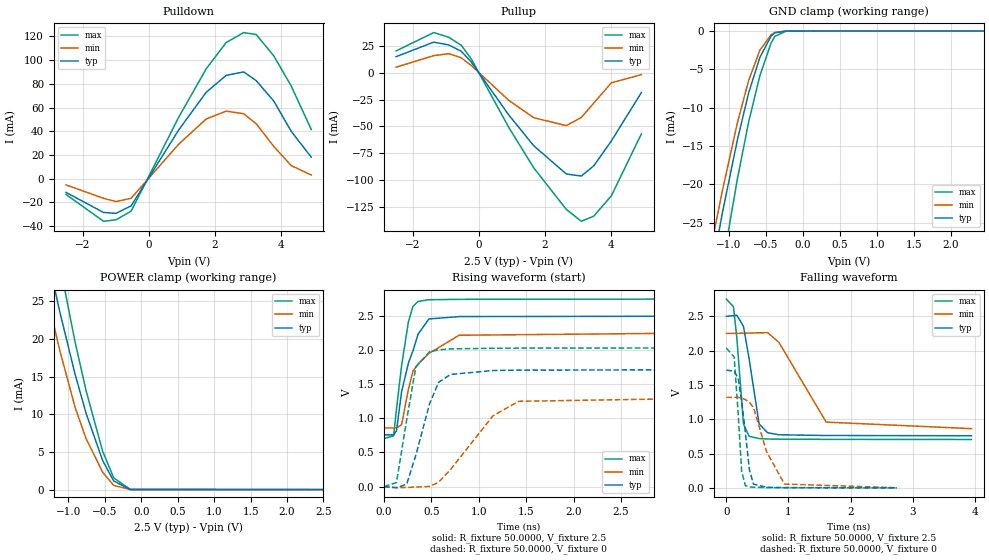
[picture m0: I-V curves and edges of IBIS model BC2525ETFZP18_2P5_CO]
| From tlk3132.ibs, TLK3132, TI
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[Model]   BC2525ETFZP18_2P5_CO
Model_type   I/O
Polarity   Non-Inverting
Enable   Active-Low
Vinl =  0.7V
Vinh =  1.7V
Cref =  15.0000pF
Rref =  100.0000M
Vref =  0V
Vmeas =  1.25
C_comp   2.309127p   2.203225p   2.349335p
[Model Spec]
Vinl   0.7V   0.7V   0.7V
Vinh   1.7V   1.7V   1.7V
[Temperature Range]   25   105   0
[Voltage Range]   2.5   2.25   2.75
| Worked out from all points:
|   slope of the pulldown table from 0 to 0.375 V, typ, clamps not added: 21.4 ohm
|   slope of the pullup table from 0 to 0.375 V, typ, clamps not added: 22.5 ohm
|   GND clamp passes 1 mA (typ) near -0.45 V on its own axis
|   POWER clamp passes 1 mA (typ) near -0.36 V on its own axis
|   rising waveform, R_fixture 50.0000, V_fixture 2.5: 20-80 % time 181ps typ, 269ps min, 118ps max; typ from 0.759 V to 2.5 V
|   rising waveform, R_fixture 50.0000, V_fixture 0: 20-80 % time 203ps typ, 452ps min, 132ps max; typ from 0 V to 1.72 V
|   falling waveform, R_fixture 50.0000, V_fixture 2.5: 20-80 % time 170ps typ, 464ps min, 103ps max; typ from 2.5 V to 0.759 V
|   falling waveform, R_fixture 50.0000, V_fixture 0: 20-80 % time 129ps typ, 290ps min, 78.3ps max; typ from 1.72 V to 0.001 V
[POWER_clamp]
|   voltage   I(typ)   I(min)   I(max)
-2.5V     103mA      79.59mA    127.2mA
-1.414V   37.89mA    31.01mA    46.59mA
-1.389V   36.5mA     29.9mA     44.97mA
-1.263V   30.03mA    24.43mA    37.51mA
-1.136V   24.34mA    19.18mA    30.79mA
-1.111V   23.3mA     18.19mA    29.51mA
-909.1mV  15.33mA    10.94mA    19.61mA
-757.6mV  10.13mA    6.766mA    13.14mA
-530.3mV  3.861mA    2.319mA    5.098mA
-378.8mV  1.145mA    563.9uA    1.555mA
-151.5mV  13.13uA    4.646uA    27.22uA
2.5V      48.25nA    100nA      297nA
[Pulldown]
|   voltage   I(typ)   I(min)   I(max)
-2.5V     -11.51mA   -5.201mA   -13.26mA
-1.364V   -28.43mA   -16.49mA   -35.86mA
-984.8mV  -29.1mA    -19.21mA   -34.52mA
-530.3mV  -22.86mA   -16.47mA   -27.32mA
909.1mV   41.11mA    29.14mA    51.82mA
1.742V    72.89mA    50.39mA    92.67mA
2.348V    87.23mA    57.05mA    114.9mA
2.879V    90.11mA    54.86mA    123.3mA
3.258V    82.75mA    46.36mA    121.6mA
3.788V    65.57mA    27.35mA    103.7mA
4.318V    40.02mA    11.1mA     78.22mA
4.924V    18.22mA    3.195mA    41.6mA
[Pullup]
|   voltage   I(typ)   I(min)   I(max)
-2.5V     15.14mA    5.324mA    20.54mA
-1.364V   28.73mA    16.09mA    37.65mA
-909.1mV  26.11mA    17.93mA    33.27mA
-530.3mV  20.16mA    14.07mA    25.77mA
-227.3mV  10.18mA    6.927mA    13.07mA
909.1mV   -39.37mA   -25.74mA   -51mA
1.667V    -68.19mA   -41.92mA   -88.83mA
2.652V    -94.51mA   -49.32mA   -127.6mA
3.106V    -96.42mA   -41.67mA   -138.7mA
3.485V    -86.79mA   -28.14mA   -133.8mA
4.015V    -63.64mA   -9.302mA   -114.9mA
4.924V    -18.43mA   -1.644mA   -57.08mA
[GND_clamp]
|   voltage   I(typ)   I(min)   I(max)
-2.5V     -116.2mA   -90.94mA   -142.3mA
-1.338V   -38.29mA   -32.95mA   -46.66mA
-1.237V   -32.01mA   -28mA      -39.68mA
-1.136V   -26.24mA   -23.14mA   -33.46mA
-1.086V   -23.65mA   -20.78mA   -30.54mA
-883.8mV  -14.17mA   -11.94mA   -19.27mA
-732.3mV  -8.082mA   -6.459mA   -11.87mA
-580.8mV  -3.458mA   -2.524mA   -5.849mA
-429.3mV  -675uA     -501.2uA   -1.581mA
-378.8mV  -238.8uA   -197.2uA   -699.9uA
-227.3mV  -10.88uA   -11uA      -30.03uA
2.449V    3.342nA    24.03uA    91.08nA
[Ramp]
| variable   typ   min   max
dV/dt_f   1.057917/0.169422n   0.8442267/0.4696358n   1.236219/0.1031428n
dV/dt_r   1.045516/0.2054243n  0.8092633/0.4608445n   1.23592/0.1329528n
R_load = 50
[Rising Waveform]
R_fixture = 50.0000
V_fixture = 2.5
V_fixture_min = 2.25
V_fixture_max = 2.75
|   time   V(typ)   V(min)   V(max)
0s        759.1mV    860.8mV    704.6mV
102ps     757.4mV    860.8mV    745.6mV
132ps     816.5mV    860.7mV    1.134V
186ps     1.39V      906.8mV    1.773V
258ps     1.813V     1.43V      2.418V
306ps     1.991V     1.693V     2.644V
360ps     2.236V     1.799V     2.716V
474ps     2.459V     1.953V     2.741V
792ps     2.494V     2.22V      2.747V
2.97ns    2.499V     2.248V     2.75V
[Rising Waveform]
R_fixture = 50.0000
V_fixture = 0
V_fixture_min = 0
V_fixture_max = 0
|   time   V(typ)   V(min)   V(max)
0s        45.2uV     17.27uV    78.37uV
132ps     -18.97mV   -13.15mV   58.56mV
240ps     35.35mV    -13.65mV   982.2mV
336ps     457.7mV    -6.885mV   1.753V
480ps     1.21V      1.607mV    1.977V
576ps     1.53V      61.71mV    2.006V
702ps     1.645V     250.3mV    2.02V
1.152ns   1.703V     1.041V     2.029V
1.422ns   1.708V     1.251V     2.031V
4.404ns   1.716V     1.317V     2.035V
[Falling Waveform]
R_fixture = 50.0000
V_fixture = 2.5
V_fixture_min = 2.25
V_fixture_max = 2.75
|   time   V(typ)   V(min)   V(max)
0s        2.5V       2.25V      2.75V
114ps     2.509V     2.251V     2.641V
168ps     2.516V     2.252V     2.198V
276ps     2.353V     2.253V     933.6mV
366ps     1.887V     2.255V     752.6mV
528ps     930.2mV    2.26V      718mV
666ps     802.9mV    2.261V     712.3mV
846ps     773.6mV    2.121V     710mV
1.608ns   763mV      958mV      707mV
3.948ns   759.3mV    863.1mV    704.8mV
[Falling Waveform]
R_fixture = 50.0000
V_fixture = 0
V_fixture_min = 0
V_fixture_max = 0
|   time   V(typ)   V(min)   V(max)
0s        1.716V     1.319V     2.036V
126ps     1.698V     1.319V     1.908V
192ps     1.595V     1.317V     1.067V
246ps     1.263V     1.308V     245.1mV
306ps     810.5mV    1.286V     33.03mV
372ps     261mV      1.246V     14.26mV
438ps     54.65mV    1.17V      9.532mV
648ps     8.61mV     528.1mV    3.99mV
936ps     4.158mV    55.55mV    2.047mV
2.748ns   1.02mV     2.275mV    289.4uV
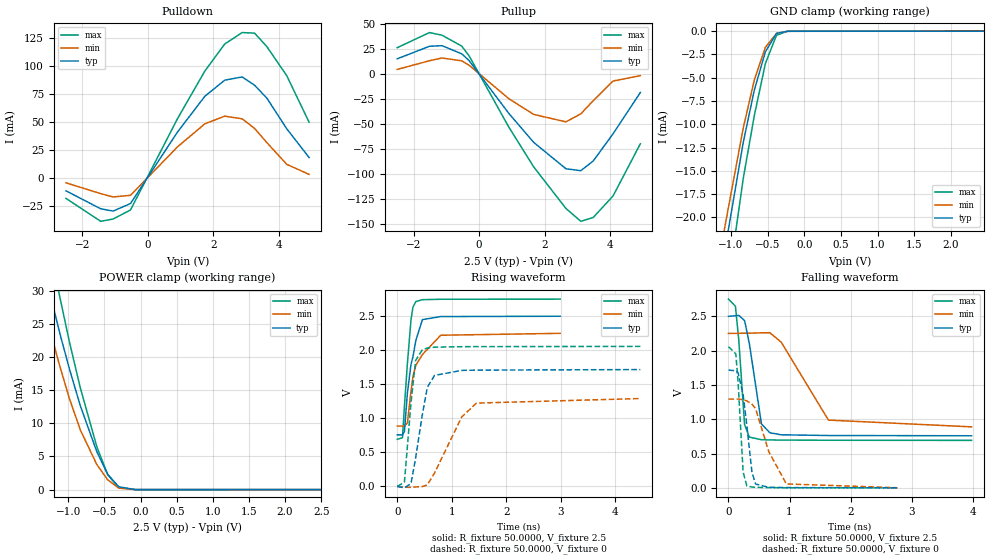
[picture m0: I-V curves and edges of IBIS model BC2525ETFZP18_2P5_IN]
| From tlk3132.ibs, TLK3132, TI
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|   Model Cell BC2525ETFZP18_2P5_IN
|BC2525ETFZP18_2P5
[Model]   BC2525ETFZP18_2P5_IN
Model_type   I/O
Polarity   Non-Inverting
Enable   Active-Low
Vinl =  0.7V
Vinh =  1.7V
Cref =  15.0000pF
Rref =  100.0000M
Vref =  0V
Vmeas =  1.25
C_comp   2.309127p   2.211398p   2.342242p
[Model Spec]
Vinl   0.7V   0.7V   0.7V
Vinh   1.7V   1.7V   1.7V
[Temperature Range]   25   125   -40
[Voltage Range]   2.5   2.25   2.75
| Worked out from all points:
|   slope of the pulldown table from 0 to 0.375 V, typ, clamps not added: 21.4 ohm
|   slope of the pullup table from 0 to 0.375 V, typ, clamps not added: 22.5 ohm
|   GND clamp passes 1 mA (typ) near -0.45 V on its own axis
|   POWER clamp passes 1 mA (typ) near -0.36 V on its own axis
|   rising waveform, R_fixture 50.0000, V_fixture 2.5: 20-80 % time 181ps typ, 272ps min, 113ps max; typ from 0.759 V to 2.5 V
|   rising waveform, R_fixture 50.0000, V_fixture 0: 20-80 % time 204ps typ, 470ps min, 121ps max; typ from 0 V to 1.72 V
|   falling waveform, R_fixture 50.0000, V_fixture 2.5: 20-80 % time 170ps typ, 476ps min, 94.6ps max; typ from 2.5 V to 0.759 V
|   falling waveform, R_fixture 50.0000, V_fixture 0: 20-80 % time 130ps typ, 293ps min, 75.4ps max; typ from 1.72 V to 0.001 V
[POWER_clamp]
|   voltage   I(typ)   I(min)   I(max)
-2.5V     103mA      77mA       124.9mA
-1.389V   36.5mA     29.6mA     43.7mA
-1.364V   35.11mA    28.54mA    42.24mA
-1.237V   28.84mA    23.35mA    35.37mA
-1.111V   23.3mA     18.37mA    28.7mA
-984.8mV  18.21mA    13.73mA    22.28mA
-833.3mV  12.63mA    8.988mA    15.33mA
-606.1mV  5.731mA    3.798mA    6.501mA
-454.5mV  2.303mA    1.469mA    2.233mA
-303mV    430uA      224.9uA    328.4uA
-75.76mV  1.022uA    1.09uA     373.5nA
2.5V      48.25nA    187.9nA    78.52nA
[Pulldown]
|   voltage   I(typ)   I(min)   I(max)
-2.5V     -11.51mA   -4.358mA   -18.24mA
-1.439V   -27.53mA   -14.02mA   -38.69mA
-1.061V   -29.57mA   -16.96mA   -36.64mA
-530.3mV  -22.86mA   -15.51mA   -28.6mA
909.1mV   41.11mA    27.83mA    53.08mA
1.742V    72.89mA    48.31mA    95.41mA
2.348V    87.24mA    55.12mA    119.5mA
2.879V    90.11mA    52.76mA    129.7mA
3.258V    82.75mA    44.23mA    129.2mA
3.636V    71.14mA    31.46mA    117.1mA
4.242V    43.83mA    12.12mA    91.2mA
4.924V    18.23mA    3.165mA    49.73mA
[Pullup]
|   voltage   I(typ)   I(min)   I(max)
-2.5V     15.14mA    4.581mA    26.25mA
-1.515V   27.67mA    13.2mA     41.32mA
-1.136V   28.26mA    15.97mA    38.74mA
-530.3mV  20.16mA    13.13mA    27.83mA
-303mV    13.29mA    8.656mA    17.98mA
909.1mV   -39.37mA   -24.63mA   -53.05mA
1.667V    -68.19mA   -40.33mA   -92.6mA
2.652V    -94.51mA   -47.7mA    -134.1mA
3.106V    -96.42mA   -39.75mA   -146.9mA
3.485V    -86.79mA   -26.62mA   -143.1mA
4.091V    -59.62mA   -7.005mA   -121.6mA
4.924V    -18.43mA   -1.635mA   -69.59mA
[GND_clamp]
|   voltage   I(typ)   I(min)   I(max)
-2.5V     -116.2mA   -88.1mA    -139.9mA
-1.338V   -38.29mA   -32.77mA   -45.08mA
-1.288V   -35.07mA   -30.39mA   -41.92mA
-1.237V   -32.01mA   -28.03mA   -38.88mA
-1.136V   -26.24mA   -23.37mA   -32.85mA
-1.086V   -23.65mA   -21.1mA    -29.88mA
-833.3mV  -11.97mA   -10.43mA   -15.85mA
-681.8mV  -6.338mA   -5.243mA   -9.07mA
-530.3mV  -2.211mA   -1.734mA   -3.467mA
-378.8mV  -238.8uA   -245.9uA   -430.9uA
-227.3mV  -10.88uA   -15.38uA   -15.83uA
2.449V    3.343nA    36.11uA    41.83nA
[Ramp]
| variable   typ   min   max
dV/dt_f   1.057951/0.1693632n  0.8284071/0.4810959n   1.244731/95.26762p
dV/dt_r   1.045398/0.2060787n  0.7933716/0.4786505n   1.248755/0.1217709n
R_load = 50
[Rising Waveform]
R_fixture = 50.0000
V_fixture = 2.5
V_fixture_min = 2.25
V_fixture_max = 2.75
|   time   V(typ)   V(min)   V(max)
0s        759mV      886.7mV    692.1mV
96ps      757.5mV    886.6mV    715.9mV
132ps     805.4mV    886.6mV    1.179V
186ps     1.369V     930.7mV    1.798V
252ps     1.791V     1.394V     2.444V
288ps     1.902V     1.613V     2.631V
342ps     2.147V     1.782V     2.715V
462ps     2.449V     1.937V     2.742V
798ps     2.494V     2.22V      2.748V
2.988ns   2.499V     2.248V     2.75V
[Rising Waveform]
R_fixture = 50.0000
V_fixture = 0
V_fixture_min = 0
V_fixture_max = 0
|   time   V(typ)   V(min)   V(max)
0s        45.2uV     18.9uV     81.41uV
132ps     -20.04mV   -10.69mV   64.09mV
252ps     42.94mV    -13.13mV   1.223V
336ps     410.8mV    -7.215mV   1.848V
462ps     1.064V     -735.1uV   2.008V
552ps     1.455V     23.24mV    2.032V
684ps     1.63V      198.4mV    2.045V
1.182ns   1.704V     1.019V     2.052V
1.452ns   1.708V     1.224V     2.053V
4.458ns   1.716V     1.291V     2.056V
[Falling Waveform]
R_fixture = 50.0000
V_fixture = 2.5
V_fixture_min = 2.25
V_fixture_max = 2.75
|   time   V(typ)   V(min)   V(max)
0s        2.5V       2.25V      2.75V
114ps     2.508V     2.251V     2.646V
168ps     2.514V     2.252V     2.161V
264ps     2.438V     2.253V     921.4mV
342ps     2.103V     2.254V     739.4mV
540ps     932.5mV    2.259V     701.9mV
678ps     803.1mV    2.261V     698.3mV
864ps     773.3mV    2.123V     696.5mV
1.638ns   762.9mV    987.6mV    693.8mV
3.984ns   759.2mV    889mV      692.1mV
[Falling Waveform]
R_fixture = 50.0000
V_fixture = 0
V_fixture_min = 0
V_fixture_max = 0
|   time   V(typ)   V(min)   V(max)
0s        1.716V     1.293V     2.057V
120ps     1.706V     1.293V     1.952V
156ps     1.68V      1.294V     1.562V
240ps     1.359V     1.285V     230.6mV
300ps     916.3mV    1.267V     29.64mV
384ps     231.4mV    1.22V      12.15mV
444ps     55.77mV    1.155V     8.632mV
660ps     8.457mV    529.2mV    3.499mV
948ps     4.117mV    57.37mV    1.807mV
2.766ns   1.011mV    2.28mV     225.2uV
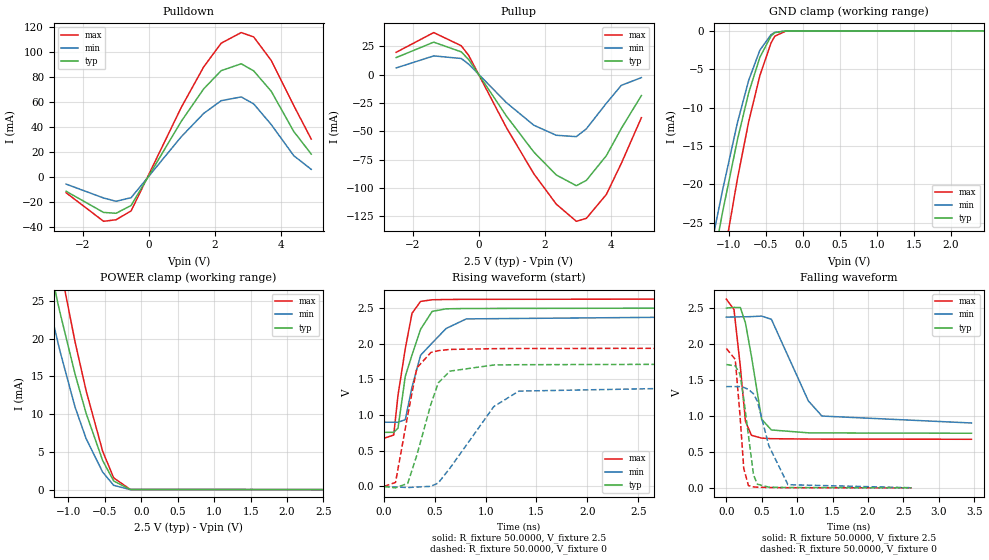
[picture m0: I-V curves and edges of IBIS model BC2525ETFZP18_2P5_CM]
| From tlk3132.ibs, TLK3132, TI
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|   Model Cell BC2525ETFZP18_2P5_CM
|BC2525ETFZP18_2P5
[Model]   BC2525ETFZP18_2P5_CM
Model_type   I/O
Polarity   Non-Inverting
Enable   Active-Low
Vinl =  0.7V
Vinh =  1.7V
Cref =  15.0000pF
Rref =  100.0000M
Vref =  0V
Vmeas =  1.25
C_comp   2.309127p   2.20323p   2.349335p
[Model Spec]
Vinl   0.7V   0.7V   0.7V
Vinh   1.7V   1.7V   1.7V
[Temperature Range]   25   105   0
[Voltage Range]   2.5   2.375   2.625
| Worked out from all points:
|   slope of the pulldown table from 0 to 0.375 V, typ, clamps not added: 21.4 ohm
|   slope of the pullup table from 0 to 0.375 V, typ, clamps not added: 22.5 ohm
|   GND clamp passes 1 mA (typ) near -0.45 V on its own axis
|   POWER clamp passes 1 mA (typ) near -0.36 V on its own axis
|   rising waveform, R_fixture 50.0000, V_fixture 2.5: 20-80 % time 182ps typ, 266ps min, 123ps max; typ from 0.759 V to 2.5 V
|   rising waveform, R_fixture 50.0000, V_fixture 0: 20-80 % time 205ps typ, 422ps min, 138ps max; typ from 0 V to 1.72 V
|   falling waveform, R_fixture 50.0000, V_fixture 2.5: 20-80 % time 168ps typ, 374ps min, 111ps max; typ from 2.5 V to 0.76 V
|   falling waveform, R_fixture 50.0000, V_fixture 0: 20-80 % time 129ps typ, 254ps min, 84ps max; typ from 1.72 V to 0.001 V
[POWER_clamp]
|   voltage   I(typ)   I(min)   I(max)
-2.5V     103mA      79.53mA    127.3mA
-1.414V   37.89mA    30.99mA    46.6mA
-1.389V   36.5mA     29.89mA    44.97mA
-1.263V   30.03mA    24.43mA    37.5mA
-1.136V   24.34mA    19.18mA    30.78mA
-1.111V   23.3mA     18.19mA    29.49mA
-909.1mV  15.33mA    10.95mA    19.6mA
-757.6mV  10.13mA    6.776mA    13.14mA
-530.3mV  3.861mA    2.322mA    5.096mA
-378.8mV  1.145mA    564.4uA    1.555mA
-151.5mV  13.13uA    4.657uA    27.15uA
2.5V      48.25nA    111nA      227.3nA
[Pulldown]
|   voltage   I(typ)   I(min)   I(max)
-2.5V     -11.51mA   -5.757mA   -12.67mA
-1.364V   -28.43mA   -16.89mA   -35.52mA
-984.8mV  -29.1mA    -19.51mA   -34.27mA
-530.3mV  -22.86mA   -16.64mA   -27.18mA
984.8mV   44.29mA    31.99mA    55.37mA
1.667V    70.38mA    50.75mA    87.97mA
2.197V    84.93mA    60.93mA    106.9mA
2.803V    90.44mA    63.93mA    115.4mA
3.182V    84.75mA    58.34mA    111.9mA
3.712V    68.49mA    41.85mA    93.11mA
4.394V    36.35mA    16.97mA    57.06mA
4.924V    18.23mA    6.01mA     30.21mA
[Pullup]
|   voltage   I(typ)   I(min)   I(max)
-2.5V     15.14mA    5.998mA    19.78mA
-1.364V   28.73mA    16.61mA    37.19mA
-530.3mV  20.16mA    14.32mA    25.57mA
-303mV    13.29mA    9.29mA     16.92mA
833.3mV   -36.25mA   -24.5mA    -46.44mA
1.667V    -68.19mA   -44.56mA   -87.35mA
2.348V    -88.45mA   -53.4mA    -114.2mA
2.955V    -97.88mA   -54.63mA   -129.3mA
3.258V    -93.2mA    -47.74mA   -126.7mA
3.864V    -71.41mA   -25.16mA   -105.6mA
4.318V    -47.32mA   -9.369mA   -78.13mA
4.924V    -18.43mA   -2.547mA   -37.92mA
[GND_clamp]
|   voltage   I(typ)   I(min)   I(max)
-2.5V     -116.2mA   -90.95mA   -142.3mA
-1.338V   -38.29mA   -32.95mA   -46.65mA
-1.237V   -32.01mA   -28.01mA   -39.66mA
-1.136V   -26.24mA   -23.15mA   -33.44mA
-1.086V   -23.65mA   -20.79mA   -30.51mA
-883.8mV  -14.17mA   -11.95mA   -19.25mA
-732.3mV  -8.082mA   -6.466mA   -11.86mA
-580.8mV  -3.458mA   -2.527mA   -5.842mA
-429.3mV  -675uA     -501.9uA   -1.578mA
-378.8mV  -238.8uA   -197.6uA   -698.3uA
-227.3mV  -10.88uA   -11.35uA   -28.95uA
2.449V    3.344nA    955.1nA    77.52nA
[Ramp]
| variable   typ   min   max
dV/dt_f   1.058002/0.1692318n   0.896552/0.3767048n   1.179064/0.1117331n
dV/dt_r   1.045161/0.2074829n  0.8614232/0.4300688n   1.17882/0.1396833n
R_load = 50
[Rising Waveform]
R_fixture = 50.0000
V_fixture = 2.5
V_fixture_min = 2.375
V_fixture_max = 2.625
|   time   V(typ)   V(min)   V(max)
0s        759mV      900mV      675.3mV
96ps      757.9mV    899.9mV    720.5mV
138ps     816.2mV    900mV      1.276V
210ps     1.544V     936.3mV    1.933V
276ps     1.843V     1.393V     2.426V
360ps     2.202V     1.838V     2.593V
474ps     2.453V     2.011V     2.616V
612ps     2.489V     2.214V     2.62V
810ps     2.494V     2.348V     2.622V
2.934ns   2.499V     2.373V     2.625V
[Rising Waveform]
R_fixture = 50.0000
V_fixture = 0
V_fixture_min = 0
V_fixture_max = 0
|   time   V(typ)   V(min)   V(max)
0s        45.2uV     20.19uV    68.04uV
114ps     -19.63mV   -6.639mV   56.64mV
234ps     43.26mV    -15.39mV   1.002V
324ps     440.2mV    -8.142mV   1.662V
462ps     1.154V     1.916mV    1.878V
534ps     1.45V      48.84mV    1.903V
648ps     1.616V     253.9mV    1.92V
1.08ns    1.702V     1.119V     1.931V
1.326ns   1.706V     1.336V     1.933V
3.996ns   1.716V     1.406V     1.938V
[Falling Waveform]
R_fixture = 50.0000
V_fixture = 2.5
V_fixture_min = 2.375
V_fixture_max = 2.625
|   time   V(typ)   V(min)   V(max)
0s        2.5V       2.375V     2.625V
108ps     2.51V      2.377V     2.481V
198ps     2.508V     2.379V     1.684V
270ps     2.293V     2.379V     926.2mV
354ps     1.834V     2.382V     731.3mV
498ps     954.9mV    2.389V     692.1mV
636ps     805.7mV    2.345V     684mV
1.158ns   765.5mV    1.21V      679.2mV
1.35ns    764.1mV    999.1mV    678.5mV
3.462ns   759.7mV    902.4mV    676mV
[Falling Waveform]
R_fixture = 50.0000
V_fixture = 0
V_fixture_min = 0
V_fixture_max = 0
|   time   V(typ)   V(min)   V(max)
0s        1.716V     1.409V     1.939V
126ps     1.696V     1.409V     1.787V
192ps     1.583V     1.408V     1.022V
246ps     1.24V      1.397V     271.7mV
312ps     730.8mV    1.369V     31.84mV
384ps     181.2mV    1.308V     13.08mV
438ps     51.49mV    1.204V     9.482mV
600ps     10.2mV     586.6mV    4.811mV
870ps     4.769mV    44.35mV    2.246mV
2.616ns   1.108mV    2.402mV    309.7uV
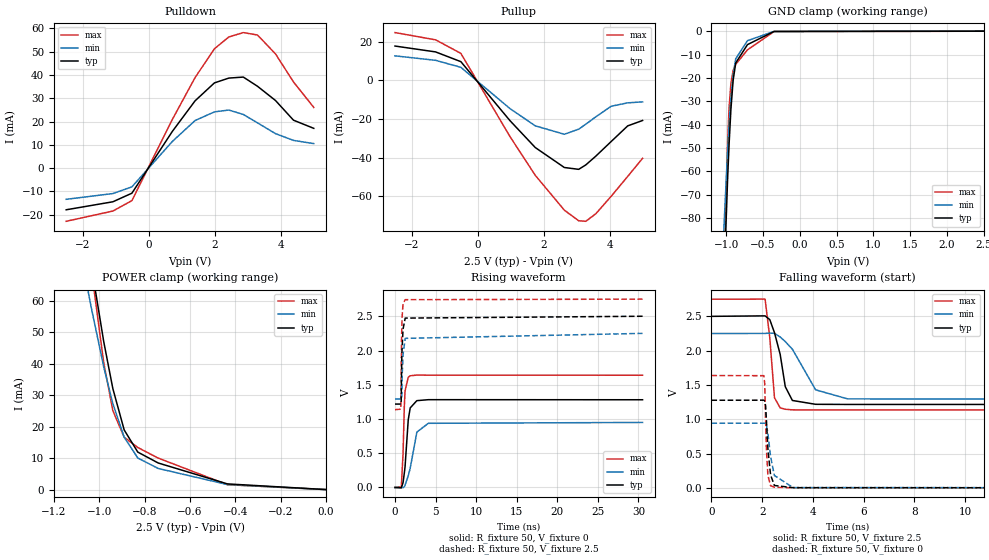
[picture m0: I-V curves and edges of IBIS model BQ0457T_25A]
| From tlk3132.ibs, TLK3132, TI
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[Model]   BQ0457T_25A
Model_type  I/O
Vinl=0.7
Vinh=1.7
Enable   Active-Low
Vref =   0
Rref =   500
Cref =   50p
Vmeas =   1.5
| variable   typ   min   max
C_comp   1.40pF   1.14pF   1.89pF
| C_pullup   1.47pF   0.67pF   2.83pF
| C_pulldown   1.40pF   0.61pF   2.70pF
| C_tri-state   1.40pF   1.14pF   1.89pF
[Temperature Range]   40   100   -40
| Ambient temperature   25   85   -40
[Voltage range]   2.5   2.25   2.75
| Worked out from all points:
|   slope of the pulldown table from 0 to 0.375 V, typ, clamps not added: 44.3 ohm
|   slope of the pullup table from 0 to 0.375 V, typ, clamps not added: 45.4 ohm
|   GND clamp passes 1 mA (typ) near -0.48 V on its own axis
|   POWER clamp passes 1 mA (typ) near -0.37 V on its own axis
|   rising waveform, R_fixture 50, V_fixture 0: 20-80 % time 467ps typ, 884ps min, 259ps max; typ from 0 V to 1.28 V
|   falling waveform, R_fixture 50, V_fixture 2.5: 20-80 % time 411ps typ, 894ps min, 205ps max; typ from 2.5 V to 1.22 V
|   rising waveform, R_fixture 50, V_fixture 2.5: 20-80 % time 170ps typ, 216ps min, 116ps max; typ from 1.22 V to 2.5 V
|   falling waveform, R_fixture 50, V_fixture 0: 20-80 % time 143ps typ, 236ps min, 83.3ps max; typ from 1.28 V to 0 V
[GND Clamp]
| BQ0457T_25A
|   Voltage   I(typ)   I(min)   I(max)
-2.5V     -2.302A    -1.754A    -3.272A
-1.06V    -139.3mA   -107.1mA   -146.5mA
-1.03V    -108.3mA   -84.38mA   -103.3mA
-1.025V   -103.3mA   -80.77mA   -96.71mA
-980mV    -63.23mA   -51.26mA   -47.2mA
-960mV    -48.42mA   -40.24mA   -32.88mA
-935mV    -33.38mA   -28.77mA   -22.3mA
-905mV    -21.09mA   -18.75mA   -16.8mA
-870mV    -13.61mA   -11.81mA   -14.19mA
-710mV    -5.738mA   -4.048mA   -7.982mA
-350mV    -111.8uA   -74.72uA   -161.4uA
2.5V      6.026uA    176.7uA    977.5nA
[POWER Clamp]
| BQ0457T_25A
|   Voltage   I(typ)   I(min)   I(max)
-2.5V     904mA      726mA      1.161A
-1.08V    93.1mA     74.92mA    98.47mA
-1.07V    88.15mA    71.04mA    91.99mA
-1.04V    73.65mA    59.7mA     73.19mA
-1.035V   71.3mA     57.86mA    70.17mA
-980mV    47.01mA    38.97mA    40.3mA
-940mV    32.13mA    27.36mA    25.12mA
-890mV    18.97mA    16.66mA    16.66mA
-830mV    11.93mA    10.05mA    13.39mA
-740mV    8.463mA    6.722mA    10.02mA
-435mV    1.816mA    1.601mA    1.556mA
-31.15fV  6.026uA    3.143uA    11.59uA
[Pulldown]
| BQ0457T_25A
|   Voltage   I(typ)   I(min)   I(max)
-2.5V     -17.9mA    -13.4mA    -22.85mA
-1.085V   -14.46mA   -10.93mA   -18.44mA
-510mV    -10.78mA   -8.055mA   -13.96mA
715mV     15.76mA    11.44mA    20.9mA
1.405V    28.92mA    20.45mA    38.91mA
1.99V     36.61mA    24.16mA    51.26mA
2.425V    38.67mA    24.94mA    56.33mA
2.865V    39.11mA    23.06mA    58.23mA
3.295V    35.16mA    19.44mA    57.18mA
3.84V     29.05mA    14.81mA    49.08mA
4.385V    20.59mA    11.9mA     37.03mA
5V        17.08mA    10.53mA    26.06mA
[Pullup]
| BQ0457T_25A
|   Voltage   I(typ)   I(min)   I(max)
-2.5V     17.67mA    12.6mA     24.64mA
-1.27V    14.64mA    10.29mA    20.88mA
-505mV    9.602mA    6.677mA    13.88mA
985mV     -20.93mA   -14.69mA   -29.18mA
1.75V     -34.8mA    -23.58mA   -49.16mA
2.63V     -45.11mA   -27.93mA   -67.17mA
3.065V    -46.06mA   -25.29mA   -72.65mA
3.28V     -43.77mA   -22.73mA   -72.92mA
3.585V    -39.21mA   -18.89mA   -69mA
4.05V     -31.66mA   -13.44mA   -59.96mA
4.55V     -23.59mA   -11.69mA   -49.7mA
5V        -20.81mA   -11.18mA   -40.37mA
[Ramp]
| BQ0457T_25A
| variable   typ   min   max
dV/dt_r   0.77/4.77E-10   0.57/8.95E-10   0.99/2.61E-10
dV/dt_f   0.78/4.23E-10   0.59/9.13E-10   0.97/2.07E-10
R_load = 50
[Rising Waveform]
| BQ0457T_25A
R_fixture =   50
C_fixture =   0
L_fixture =   0
V_fixture =   0
V_fixture_min = 0
V_fixture_max = 0
|   Time   V(typ)   V(min)   V(max)
0s        79.95uV    52.4uV     139.2uV
780ps     -5.3mV     -84.59uV   13.4mV
990ps     69.58mV    -2.339mV   485.7mV
1.15ns    211.2mV    10.03mV    1.185V
1.24ns    304.6mV    34.15mV    1.411V
1.635ns   991.4mV    171.4mV    1.61V
1.875ns   1.162V     281.8mV    1.631V
2.695ns   1.268V     809.2mV    1.641V
4.11ns    1.282V     937.1mV    1.64V
30.51ns   1.281V     949.9mV    1.639V
[Falling Waveform]
| BQ0457T_25A
R_fixture =   50
C_fixture =   0
L_fixture =   0
V_fixture =   2.5
V_fixture_min = 2.25
V_fixture_max = 2.75
|   Time   V(typ)   V(min)   V(max)
0s        2.5V       2.25V      2.75V
2.115ns   2.507V     2.251V     2.751V
2.3ns     2.452V     2.256V     2.188V
2.485ns   2.262V     2.252V     1.313V
2.71ns    1.944V     2.199V     1.166V
2.91ns    1.475V     2.132V     1.146V
3.19ns    1.274V     2.021V     1.137V
4.105ns   1.218V     1.429V     1.136V
5.365ns   1.216V     1.297V     1.136V
30.51ns   1.215V     1.283V     1.137V
[Rising Waveform]
| BQ0457T_25A
R_fixture =   50
C_fixture =   0
L_fixture =   0
V_fixture =   2.5
V_fixture_min = 2.25
V_fixture_max = 2.75
|   Time   V(typ)   V(min)   V(max)
0s        1.218V     1.291V     1.137V
710ps     1.218V     1.291V     1.143V
730ps     1.218V     1.29V      1.234V
765ps     1.264V     1.29V      1.722V
800ps     1.636V     1.291V     2.127V
845ps     1.94V      1.343V     2.356V
885ps     2.057V     1.643V     2.505V
995ps     2.314V     1.943V     2.686V
1.26ns    2.473V     2.177V     2.742V
30.51ns   2.5V       2.25V      2.75V
[Falling Waveform]
| BQ0457T_25A
R_fixture =   50
C_fixture =   0
L_fixture =   0
V_fixture =   0
V_fixture_min = 0
V_fixture_max = 0
|   Time   V(typ)   V(min)   V(max)
0s        1.277V     942.2mV    1.637V
2.065ns   1.278V     943mV      1.635V
2.1ns     1.268V     943.9mV    1.522V
2.135ns   1.194V     939.5mV    979.1mV
2.165ns   1.002V     921.7mV    581.6mV
2.225ns   571mV      796mV      183.5mV
2.33ns    190.7mV    459mV      31.97mV
2.48ns    35mV       180.9mV    9.502mV
3.215ns   2.859mV    4.539mV    1.466mV
30.51ns   80.89uV    49.27uV    134.4uV
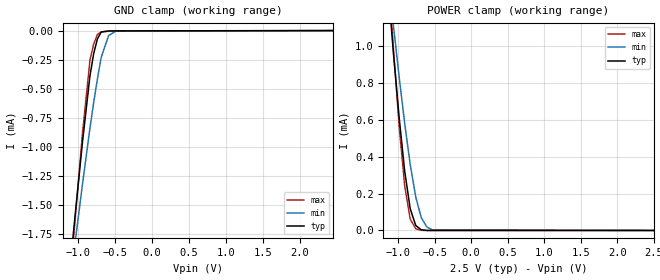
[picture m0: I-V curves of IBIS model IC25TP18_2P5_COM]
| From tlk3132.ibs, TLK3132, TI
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[Model]   IC25TP18_2P5_COM
Model_type   Input
Polarity   Non-Inverting
Vinl =  0.7V
Vinh =  1.7V
C_comp   0.5354074p   0.490933p   0.5913873p
[Model Spec]
Vinl   0.7V   0.7V   0.7V
Vinh   1.7V   1.7V   1.7V
[Temperature Range]   25   105   0
[Voltage Range]   2.5   2.25   2.75
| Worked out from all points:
|   GND clamp passes 1 mA (typ) near -0.94 V on its own axis
|   POWER clamp passes 1 mA (typ) near -1.07 V on its own axis
[POWER_clamp]
|   voltage   I(typ)   I(min)   I(max)
-2.5V     8.347mA    6.724mA    10.07mA
-1.086V   1.076mA    1.198mA    1.126mA
-1.061V   954.2uA    1.104mA    975.7uA
-1.035V   841.1uA    1.015mA    839.5uA
-984.8mV  614.8uA    835.1uA    567.1uA
-909.1mV  323.2uA    582.8uA    242.4uA
-833.3mV  118.7uA    359.1uA    62.39uA
-757.6mV  27.16uA    182.1uA    9.319uA
-681.8mV  3.612uA    70uA       911.6nA
-606.1mV  316.7nA    19.14uA    214.9nA
-530.3mV  42.27nA    3.644uA    177.2nA
2.5V      20.19nA    14.01nA    152.9nA
[GND_clamp]
|   voltage   I(typ)   I(min)   I(max)
-2.5V     -11.64mA   -9.611mA   -13.56mA
-1.136V   -2.269mA   -2.348mA   -2.443mA
-1.086V   -1.932mA   -2.088mA   -2.038mA
-1.035V   -1.6mA     -1.829mA   -1.64mA
-934.3mV  -960.6uA   -1.323mA   -883.8uA
-833.3mV  -389.9uA   -839.5uA   -254.8uA
-782.8mV  -197.5uA   -618.5uA   -114.4uA
-732.3mV  -71.7uA    -415.6uA   -33.05uA
-681.8mV  -12.36uA   -230.9uA   -10.6uA
-580.8mV  -2.879uA   -42.32uA   -5.652uA
-479.8mV  -2.348uA   -3.401uA   -5.291uA
2.449V    19.91nA    15.42nA    141.5nA
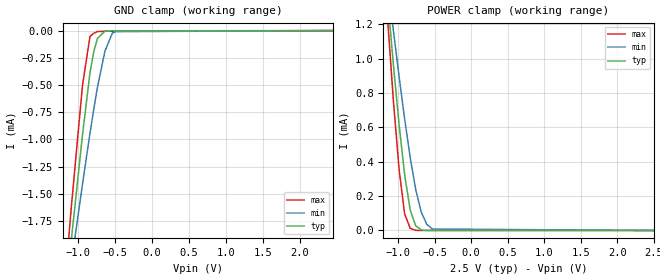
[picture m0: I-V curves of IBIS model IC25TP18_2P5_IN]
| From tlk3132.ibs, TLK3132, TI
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|   Model Cell IC25TP18_2P5_IN
|IC25TP18_2P5
[Model]   IC25TP18_2P5_IN
Model_type   Input
Polarity   Non-Inverting
Vinl =  0.7V
Vinh =  1.7V
C_comp   0.5354074p   0.4896019p   0.590865p
[Model Spec]
Vinl   0.7V   0.7V   0.7V
Vinh   1.7V   1.7V   1.7V
[Temperature Range]   25   125   -40
[Voltage Range]   2.5   2.25   2.75
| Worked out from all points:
|   GND clamp passes 1 mA (typ) near -0.94 V on its own axis
|   POWER clamp passes 1 mA (typ) near -1.07 V on its own axis
[POWER_clamp]
|   voltage   I(typ)   I(min)   I(max)
-2.5V     8.347mA    6.56mA     9.991mA
-1.136V   1.318mA    1.425mA    1.19mA
-1.111V   1.197mA    1.335mA    1.041mA
-1.061V   954.2uA    1.155mA    742.3uA
-984.8mV  614.8uA    894.6uA    353.9uA
-909.1mV  323.2uA    648uA      96.27uA
-833.3mV  118.7uA    424.4uA    12.31uA
-757.6mV  27.16uA    238.3uA    743.5nA
-681.8mV  3.612uA    106.6uA    90.26nA
-606.1mV  316.7nA    35.88uA    69.94nA
-530.3mV  42.27nA    8.561uA    68.04nA
2.5V      20.19nA    21.65nA    58.79nA
[GND_clamp]
|   voltage   I(typ)   I(min)   I(max)
-2.5V     -11.64mA   -9.341mA   -13.38mA
-1.187V   -2.612mA   -2.648mA   -2.458mA
-1.136V   -2.269mA   -2.396mA   -2.039mA
-1.086V   -1.932mA   -2.146mA   -1.631mA
-934.3mV  -960.6uA   -1.413mA   -506.7uA
-833.3mV  -389.9uA   -945.1uA   -54.51uA
-782.8mV  -197.5uA   -727.2uA   -25.12uA
-732.3mV  -71.7uA    -522.3uA   -9.03uA
-631.3mV  -6.205uA   -189.1uA   -6.039uA
-530.3mV  -2.384uA   -22.48uA   -5.91uA
-479.8mV  -2.348uA   -9.535uA   -5.888uA
2.449V    19.91nA    25.53nA    53.81nA
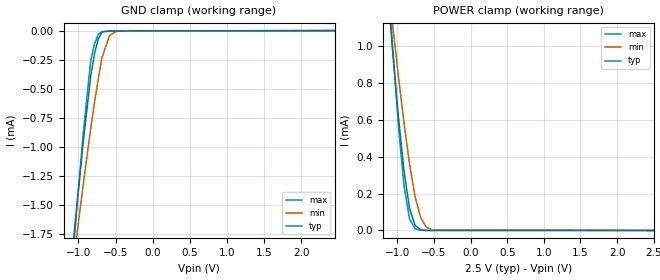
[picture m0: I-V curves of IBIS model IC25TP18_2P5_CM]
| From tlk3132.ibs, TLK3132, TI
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|   Model Cell IC25TP18_2P5_CM
|IC25TP18_2P5
[Model]   IC25TP18_2P5_CM
Model_type   Input
Polarity   Non-Inverting
Vinl =  0.7V
Vinh =  1.7V
C_comp   0.5354074p   0.490933p   0.5913873p
[Model Spec]
Vinl   0.7V   0.7V   0.7V
Vinh   1.7V   1.7V   1.7V
[Temperature Range]   25   105   0
[Voltage Range]   2.5   2.375   2.625
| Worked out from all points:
|   GND clamp passes 1 mA (typ) near -0.94 V on its own axis
|   POWER clamp passes 1 mA (typ) near -1.07 V on its own axis
[POWER_clamp]
|   voltage   I(typ)   I(min)   I(max)
-2.5V     8.347mA    6.719mA    10.08mA
-1.086V   1.076mA    1.197mA    1.126mA
-1.061V   954.2uA    1.104mA    976uA
-1.035V   841.1uA    1.014mA    839.7uA
-984.8mV  614.8uA    835uA      567.1uA
-909.1mV  323.2uA    583uA      242.3uA
-833.3mV  118.7uA    359.4uA    62.32uA
-757.6mV  27.16uA    182.3uA    9.25uA
-681.8mV  3.612uA    70.03uA    842.6nA
-606.1mV  316.7nA    19.15uA    147nA
-530.3mV  42.27nA    3.652uA    110.4nA
2.5V      20.19nA    21.04nA    93.4nA
[GND_clamp]
|   voltage   I(typ)   I(min)   I(max)
-2.5V     -11.64mA   -9.612mA   -13.56mA
-1.136V   -2.269mA   -2.349mA   -2.443mA
-1.086V   -1.932mA   -2.088mA   -2.038mA
-1.035V   -1.6mA     -1.83mA    -1.639mA
-934.3mV  -960.6uA   -1.324mA   -883.6uA
-833.3mV  -389.9uA   -839.6uA   -254.4uA
-782.8mV  -197.5uA   -618.6uA   -113.8uA
-732.3mV  -71.7uA    -415.7uA   -32.31uA
-681.8mV  -12.36uA   -231uA     -9.8uA
-580.8mV  -2.879uA   -42.43uA   -4.849uA
-479.8mV  -2.348uA   -3.527uA   -4.491uA
2.449V    19.91nA    21.42nA    89nA
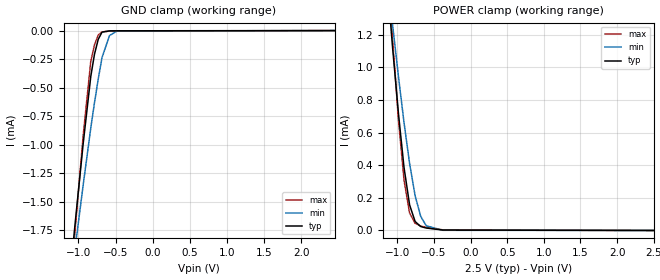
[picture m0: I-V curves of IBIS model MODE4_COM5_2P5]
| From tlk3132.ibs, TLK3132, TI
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|   Model Cell MODE4_COM5_2P5
|MODE4_COM5_2P5
[Model]   MODE4_COM5_2P5
Model_type   Input
Polarity   Non-Inverting
Vinl =  0.7V
Vinh =  1.7V
C_comp   0.5589689p   0.5151173p   0.6105178p
[Model Spec]
Vinl   0.7V   0.7V   0.7V
Vinh   1.7V   1.7V   1.7V
[Temperature Range]   25   105   0
[Voltage Range]   2.5   2.25   2.75
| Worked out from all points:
|   GND clamp passes 1 mA (typ) near -0.94 V on its own axis
|   POWER clamp passes 1 mA (typ) near -1.04 V on its own axis
[POWER_clamp]
|   voltage   I(typ)   I(min)   I(max)
-2.5V     9.467mA    7.498mA    11.6mA
-1.086V   1.236mA    1.347mA    1.317mA
-1.061V   1.099mA    1.243mA    1.145mA
-1.035V   971.1uA    1.143mA    989.4uA
-984.8mV  715.3uA    943.2uA    677.4uA
-909.1mV  386.1uA    661.8uA    308.2uA
-833.3mV  157.5uA    411.7uA    107.1uA
-757.6mV  54.91uA    213.2uA    43.82uA
-681.8mV  24.34uA    86.9uA     27.14uA
-606.1mV  15.13uA    28.83uA    19.11uA
-378.8mV  2.558uA    1.133uA    3.69uA
2.5V      20.79nA    14.3nA     154.5nA
[GND_clamp]
|   voltage   I(typ)   I(min)   I(max)
-2.5V     -11.84mA   -9.781mA   -13.79mA
-1.136V   -2.315mA   -2.39mA    -2.496mA
-1.086V   -1.972mA   -2.125mA   -2.084mA
-1.035V   -1.634mA   -1.862mA   -1.679mA
-934.3mV  -984uA     -1.348mA   -911.1uA
-833.3mV  -402.6uA   -855.5uA   -269.7uA
-782.8mV  -205.6uA   -630.5uA   -123.6uA
-732.3mV  -75.89uA   -424.1uA   -37.4uA
-681.8mV  -13.43uA   -236uA     -11.24uA
-580.8mV  -2.536uA   -43.59uA   -4.59uA
-479.8mV  -1.865uA   -3.527uA   -4.092uA
2.449V    20.28nA    49.17nA    141.5nA
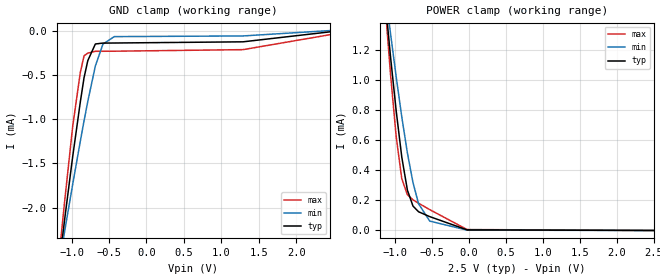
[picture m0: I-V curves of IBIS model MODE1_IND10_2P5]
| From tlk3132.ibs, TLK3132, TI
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|   Model Cell MODE1_IND10_2P5
|MODE1_IND10_2P5
[Model]   MODE1_IND10_2P5
Model_type   Input
Polarity   Non-Inverting
Vinl =  0.7V
Vinh =  1.7V
C_comp   0.5589689p   0.5140408p   0.6098818p
[Model Spec]
Vinl   0.7V   0.7V   0.7V
Vinh   1.7V   1.7V   1.7V
[Temperature Range]   25   125   -40
[Voltage Range]   2.5   2.375   2.625
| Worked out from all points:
|   GND clamp passes 1 mA (typ) near -0.92 V on its own axis
|   POWER clamp passes 1 mA (typ) near -1.03 V on its own axis
[POWER_clamp]
|   voltage   I(typ)   I(min)   I(max)
-2.5V     9.469mA    7.302mA    11.5mA
-1.111V   1.415mA    1.507mA    1.352mA
-1.086V   1.284mA    1.408mA    1.194mA
-1.061V   1.154mA    1.309mA    1.037mA
-984.8mV  795.8uA    1.023mA    624.8uA
-909.1mV  488.5uA    755.6uA    344.4uA
-833.3mV  268.9uA    516.4uA    237.9uA
-757.6mV  162.6uA    318.9uA    204uA
-681.8mV  124.4uA    177.7uA    181.4uA
-530.3mV  92.08uA    62.25uA    138.5uA
-25.25mV  4.064uA    2.307uA    6.193uA
2.5V      20.47nA    31.98nA    32.72nA
[GND_clamp]
|   voltage   I(typ)   I(min)   I(max)
-2.5V     -11.97mA   -9.559mA   -13.85mA
-1.136V   -2.439mA   -2.493mA   -2.299mA
-1.086V   -2.096mA   -2.24mA    -1.884mA
-984.8mV  -1.425mA   -1.738mA   -1.084mA
-883.8mV  -810.2uA   -1.254mA   -473uA
-833.3mV  -529.3uA   -1.018mA   -280.1uA
-782.8mV  -334.1uA   -796.9uA   -249uA
-681.8mV  -145.4uA   -394uA     -228.5uA
-580.8mV  -135.3uA   -147.3uA   -227.9uA
-429.3mV  -134.4uA   -61.88uA   -227.2uA
1.288V    -120.9uA   -54.37uA   -209.6uA
2.449V    -7.76uA    6.778uA    -40.17uA
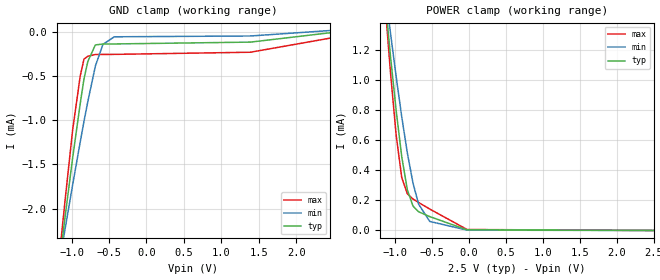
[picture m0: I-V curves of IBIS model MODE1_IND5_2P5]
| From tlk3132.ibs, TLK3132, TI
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|   Model Cell MODE1_IND5_2P5
|MODE1_IND5_2P5
[Model]   MODE1_IND5_2P5
Model_type   Input
Polarity   Non-Inverting
Vinl =  0.7V
Vinh =  1.7V
C_comp   0.5589689p   0.5140408p   0.6098818p
[Model Spec]
Vinl   0.7V   0.7V   0.7V
Vinh   1.7V   1.7V   1.7V
[Temperature Range]   25   125   -40
[Voltage Range]   2.5   2.25   2.75
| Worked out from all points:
|   GND clamp passes 1 mA (typ) near -0.92 V on its own axis
|   POWER clamp passes 1 mA (typ) near -1.03 V on its own axis
[POWER_clamp]
|   voltage   I(typ)   I(min)   I(max)
-2.5V     9.469mA    7.308mA    11.49mA
-1.111V   1.415mA    1.507mA    1.358mA
-1.086V   1.284mA    1.408mA    1.201mA
-1.061V   1.154mA    1.309mA    1.044mA
-984.8mV  795.8uA    1.022mA    631.5uA
-909.1mV  488.5uA    753.7uA    350.6uA
-833.3mV  268.9uA    513.7uA    243.6uA
-757.6mV  162.6uA    316uA      209.3uA
-681.8mV  124.4uA    175.1uA    186.2uA
-530.3mV  92.08uA    60.11uA    142.3uA
-25.25mV  4.064uA    2.176uA    6.416uA
2.5V      20.47nA    21.94nA    58.9nA
[GND_clamp]
|   voltage   I(typ)   I(min)   I(max)
-2.5V     -11.97mA   -9.551mA   -13.87mA
-1.136V   -2.439mA   -2.485mA   -2.323mA
-1.086V   -2.096mA   -2.232mA   -1.908mA
-984.8mV  -1.425mA   -1.73mA    -1.108mA
-883.8mV  -810.2uA   -1.246mA   -497.9uA
-833.3mV  -529.3uA   -1.01mA    -305.4uA
-782.8mV  -334.1uA   -788.8uA   -274.4uA
-681.8mV  -145.4uA   -385.7uA   -254uA
-580.8mV  -135.3uA   -138.8uA   -253.3uA
-429.3mV  -134.4uA   -53.27uA   -252.6uA
1.389V    -113.5uA   -44.07uA   -228.1uA
2.449V    -7.76uA    17.83uA    -68.76uA
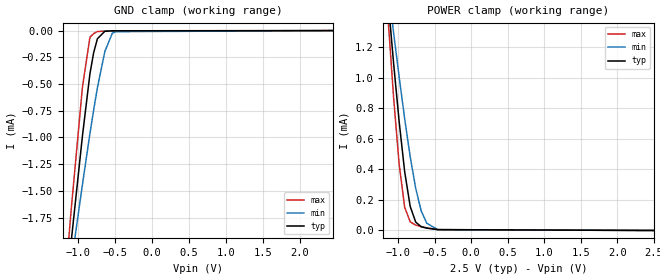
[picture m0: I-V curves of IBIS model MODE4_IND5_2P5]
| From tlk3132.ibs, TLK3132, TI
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|   Model Cell MODE4_IND5_2P5
|MODE4_IND5_2P5
[Model]   MODE4_IND5_2P5
Model_type   Input
Polarity   Non-Inverting
Vinl =  0.7V
Vinh =  1.7V
C_comp   0.5589689p   0.5140408p   0.6098818p
[Model Spec]
Vinl   0.7V   0.7V   0.7V
Vinh   1.7V   1.7V   1.7V
[Temperature Range]   25   125   -40
[Voltage Range]   2.5   2.25   2.75
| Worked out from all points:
|   GND clamp passes 1 mA (typ) near -0.94 V on its own axis
|   POWER clamp passes 1 mA (typ) near -1.04 V on its own axis
[POWER_clamp]
|   voltage   I(typ)   I(min)   I(max)
-2.5V     9.467mA    7.307mA    11.48mA
-1.136V   1.511mA    1.598mA    1.388mA
-1.111V   1.374mA    1.498mA    1.217mA
-1.061V   1.099mA    1.298mA    876.4uA
-984.8mV  715.3uA    1.008mA    436.7uA
-909.1mV  386.1uA    733.3uA    152.8uA
-833.3mV  157.5uA    483.7uA    56.6uA
-757.6mV  54.91uA    275.2uA    35.01uA
-681.8mV  24.34uA    127.3uA    25.33uA
-606.1mV  15.13uA    47.18uA    17.38uA
-454.5mV  5.622uA    4.94uA     5.63uA
2.5V      20.79nA    22.21nA    59.02nA
[GND_clamp]
|   voltage   I(typ)   I(min)   I(max)
-2.5V     -11.84mA   -9.504mA   -13.64mA
-1.187V   -2.664mA   -2.695mA   -2.516mA
-1.136V   -2.315mA   -2.438mA   -2.089mA
-1.086V   -1.972mA   -2.185mA   -1.673mA
-934.3mV  -984uA     -1.439mA   -527.5uA
-833.3mV  -402.6uA   -963uA     -61.33uA
-782.8mV  -205.6uA   -741.3uA   -27.62uA
-732.3mV  -75.89uA   -532.8uA   -8.879uA
-631.3mV  -6.376uA   -193.5uA   -4.847uA
-530.3mV  -1.911uA   -23.32uA   -4.679uA
-479.8mV  -1.865uA   -9.905uA   -4.654uA
2.449V    20.28nA    79.68nA    53.78nA
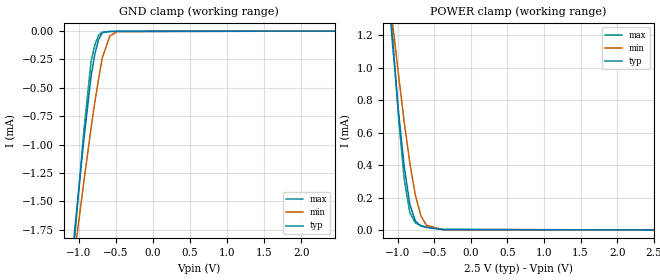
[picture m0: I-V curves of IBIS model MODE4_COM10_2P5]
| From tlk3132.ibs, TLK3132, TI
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|   Model Cell MODE4_COM10_2P5
|MODE4_COM10_2P5
[Model]   MODE4_COM10_2P5
Model_type   Input
Polarity   Non-Inverting
Vinl =  0.7V
Vinh =  1.7V
C_comp   0.5589689p   0.5151173p   0.6105178p
[Model Spec]
Vinl   0.7V   0.7V   0.7V
Vinh   1.7V   1.7V   1.7V
[Temperature Range]   25   105   0
[Voltage Range]   2.5   2.375   2.625
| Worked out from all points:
|   GND clamp passes 1 mA (typ) near -0.94 V on its own axis
|   POWER clamp passes 1 mA (typ) near -1.04 V on its own axis
[POWER_clamp]
|   voltage   I(typ)   I(min)   I(max)
-2.5V     9.467mA    7.491mA    11.61mA
-1.086V   1.236mA    1.346mA    1.318mA
-1.061V   1.099mA    1.243mA    1.146mA
-1.035V   971.1uA    1.143mA    989.7uA
-984.8mV  715.3uA    943uA      677.4uA
-909.1mV  386.1uA    661.9uA    308uA
-833.3mV  157.5uA    412uA      106.9uA
-757.6mV  54.91uA    213.4uA    43.66uA
-681.8mV  24.34uA    87uA       27uA
-606.1mV  15.13uA    28.88uA    18.99uA
-378.8mV  2.558uA    1.142uA    3.62uA
2.5V      20.79nA    21.35nA    94.88nA
[GND_clamp]
|   voltage   I(typ)   I(min)   I(max)
-2.5V     -11.84mA   -9.781mA   -13.79mA
-1.136V   -2.315mA   -2.391mA   -2.495mA
-1.086V   -1.972mA   -2.125mA   -2.084mA
-1.035V   -1.634mA   -1.863mA   -1.679mA
-934.3mV  -984uA     -1.348mA   -910.8uA
-833.3mV  -402.6uA   -855.6uA   -269.4uA
-782.8mV  -205.6uA   -630.6uA   -123.1uA
-732.3mV  -75.89uA   -424.1uA   -36.83uA
-681.8mV  -13.43uA   -236.1uA   -10.64uA
-580.8mV  -2.536uA   -43.68uA   -3.983uA
-479.8mV  -1.865uA   -3.624uA   -3.488uA
2.449V    20.28nA    23.22nA    89.28nA
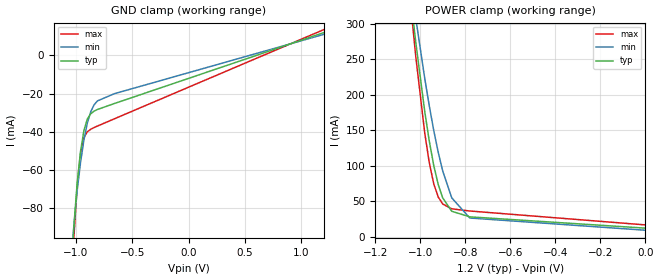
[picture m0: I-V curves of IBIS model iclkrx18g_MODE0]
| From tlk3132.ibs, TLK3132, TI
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[Model]   iclkrx18g_MODE0
Model_type   Input
Polarity   Non-Inverting
C_comp   2.6600pF   1.8070pF   2.7420pF
Vinh =   0.725V
Vinl =   0.475V
[Temperature Range]   25.0000   0.1250k   -40.0000
[Voltage Range]   1.2000V   1.0800V   1.3200V
[GND_clamp]
| voltage   I(typ)   I(min)   I(max)
-1.2V     -536mA     -388.5mA   -700.1mA
-1.05V    -122.6mA   -113.4mA   -139.2mA
-1.02V    -90.24mA   -89.56mA   -96.12mA
-990mV    -66.94mA   -70.92mA   -68.08mA
-960mV    -50.23mA   -56.04mA   -51.12mA
-930mV    -39.33mA   -44.3mA    -43.09mA
-900mV    -33.39mA   -35.52mA   -40.04mA
-870mV    -30.59mA   -29.56mA   -38.7mA
-840mV    -29.21mA   -25.94mA   -37.8mA
-810mV    -28.35mA   -23.86mA   -37.02mA
-660mV    -25.24mA   -20.09mA   -33.24mA
1.2V      11.92mA    10.97mA    13.46mA
[POWER_clamp]
| voltage   I(typ)   I(min)   I(max)
-1.2V     826.7mA    761.5mA    900.4mA
-1.1V     505.9mA    499.6mA    524.1mA
-1.06V    385.9mA    401.1mA    383.5mA
-1.02V    274.4mA    308.1mA    254.4mA
-980mV    176.4mA    223.1mA    146mA
-960mV    135mA      184.7mA    104.5mA
-940mV    100.3mA    149.7mA    74.39mA
-920mV    73.4mA     118.7mA    55.73mA
-900mV    54.51mA    92.31mA    45.94mA
-860mV    35.69mA    54.58mA    39.13mA
-780mV    27.84mA    26.21mA    36.08mA
0V        11.92mA    8.966mA    16.47mA
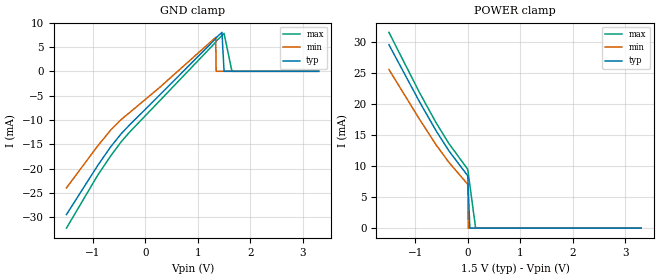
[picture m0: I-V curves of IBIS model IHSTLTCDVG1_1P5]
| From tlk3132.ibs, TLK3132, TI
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|   Model IHSTLTCDVG1_1P5
[Model]   IHSTLTCDVG1_1P5
Model_type   Input
Polarity   Non-Inverting
Vinl =   0.5500V
Vinh =   0.9500V
C_comp   0.7726pF   0.7726pF   0.7726pF
[Temperature Range]   25.0000   0.1250k   -40.0000
[Pullup Reference]   1.5000V   1.3500V   1.6500V
[Pulldown Reference]   0.000V   0.000V   0.000V
[POWER Clamp Reference]   1.5000V   1.3500V   1.6500V
[GND Clamp Reference]   0.000V   0.000V   0.000V
[GND_clamp]
| voltage   I(typ)   I(min)   I(max)
-1.5V     -29.47mA   -23.98mA   -32.26mA
-900mV    -19.3mA    -15.29mA   -21.29mA
-660mV    -15.57mA   -12.12mA   -17.45mA
-460mV    -12.87mA   -9.941mA   -14.52mA
-300mV    -11.05mA   -8.505mA   -12.53mA
260mV     -5.04mA    -3.451mA   -6.234mA
1.34V     6.698mA    6.97mA     5.975mA
1.35V     6.916mA    0A         6.202mA
1.46V     8.006mA    0A         7.335mA
1.5V      0A         0A         7.788mA
1.65V     0A         0A         0A
3.3V      0A         0A         0A
[POWER_clamp]
| voltage   I(typ)   I(min)   I(max)
-1.5V     29.59mA    25.59mA    31.58mA
-920mV    20.41mA    17.59mA    21.89mA
-600mV    15.67mA    13.4mA     16.97mA
-360mV    12.49mA    10.63mA    13.66mA
0V        8.443mA    7.067mA    9.488mA
10mV      6.332mA    0A         8.855mA
40mV      0A         0A         6.958mA
150mV     0A         0A         0A
3.3V      0A         0A         0A
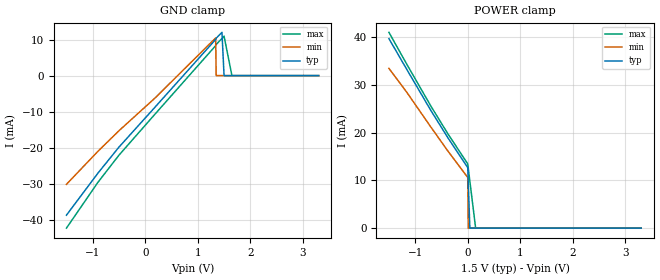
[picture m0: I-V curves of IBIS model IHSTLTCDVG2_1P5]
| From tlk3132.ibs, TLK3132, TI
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|   Model IHSTLTCDVG2_1P5
[Model]   IHSTLTCDVG2_1P5
Model_type   Input
Polarity   Non-Inverting
Vinl =   0.5500V
Vinh =   0.9500V
C_comp   0.7726pF   0.7726pF   0.7726pF
[Temperature Range]   25.0000   0.1250k   -40.0000
[Pullup Reference]   1.5000V   1.3500V   1.6500V
[Pulldown Reference]   0.000V   0.000V   0.000V
[POWER Clamp Reference]   1.5000V   1.3500V   1.6500V
[GND Clamp Reference]   0.000V   0.000V   0.000V
[GND_clamp]
| voltage   I(typ)   I(min)   I(max)
-1.5V     -38.73mA   -30.16mA   -42.32mA
-900mV    -27.05mA   -21mA      -29.6mA
-500mV    -19.83mA   -15.29mA   -22.07mA
180mV     -8.85mA    -6.296mA   -10.78mA
1.34V     10.04mA    10.45mA    8.315mA
1.35V     10.37mA    0A         8.646mA
1.46V     12mA       0A         10.3mA
1.5V      0A         0A         10.96mA
1.65V     0A         0A         0A
3.3V      0A         0A         0A
[POWER_clamp]
| voltage   I(typ)   I(min)   I(max)
-1.5V     39.63mA    33.41mA    40.94mA
-1.16V    33.19mA    28.41mA    34.27mA
-700mV    24.57mA    21.11mA    25.49mA
-380mV    18.93mA    16.15mA    19.77mA
0V        12.66mA    10.6mA     13.43mA
10mV      9.493mA    0A         12.54mA
40mV      0A         0A         9.852mA
150mV     0A         0A         0A
3.3V      0A         0A         0A
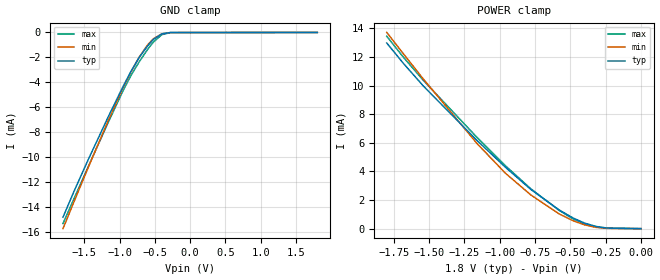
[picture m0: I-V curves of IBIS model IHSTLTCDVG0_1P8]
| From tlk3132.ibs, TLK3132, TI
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|   Model IHSTLTCDVG0_1P8
[Model]   IHSTLTCDVG0_1P8
Model_type   Input
Polarity   Non-Inverting
Vinl =   0.7000V
Vinh =   1.1000V
C_comp   0.7726pF   0.7726pF   0.7726pF
[Temperature Range]   25.0000   0.1250k   -40.0000
[Pullup Reference]   1.8000V   1.6200V   1.9500V
[Pulldown Reference]   0.000V   0.000V   0.000V
[POWER Clamp Reference]   1.8000V   1.6200V   1.9500V
[GND Clamp Reference]   0.000V   0.000V   0.000V
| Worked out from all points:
|   GND clamp passes 1 mA (typ) near -0.59 V on its own axis
|   POWER clamp passes 1 mA (typ) near -0.53 V on its own axis
[GND_clamp]
| voltage   I(typ)   I(min)   I(max)
-1.8V     -14.84mA   -15.76mA   -15.35mA
-1.64V    -12.71mA   -13.54mA   -13.3mA
-1.44V    -10.18mA   -10.81mA   -10.75mA
-1.16V    -6.784mA   -7.078mA   -7.227mA
-960mV    -4.458mA   -4.571mA   -4.797mA
-840mV    -3.145mA   -3.192mA   -3.475mA
-720mV    -1.998mA   -1.968mA   -2.351mA
-600mV    -1.064mA   -978.1uA   -1.345mA
-520mV    -560.7uA   -504.6uA   -768.9uA
-400mV    -107.2uA   -110.8uA   -177.4uA
-280mV    -7.563uA   -12.73uA   -10.59uA
1.8V      84.51nA    4.93uA     141.9nA
[POWER_clamp]
| voltage   I(typ)   I(min)   I(max)
-1.8V     12.97mA    13.71mA    13.44mA
-1.68V    11.52mA    12.19mA    11.95mA
-1.54V    9.956mA    10.44mA    10.35mA
-1.16V    6.152mA    5.937mA    6.363mA
-960mV    4.291mA    3.874mA    4.393mA
-780mV    2.738mA    2.355mA    2.784mA
-580mV    1.308mA    1.033mA    1.279mA
-480mV    740.3uA    549.4uA    679.4uA
-400mV    390.5uA    265.5uA    329.1uA
-320mV    157.6uA    90.58uA    121.3uA
-240mV    40.69uA    19.71uA    30.41uA
0V        84.51nA    70.87nA    310.1nA
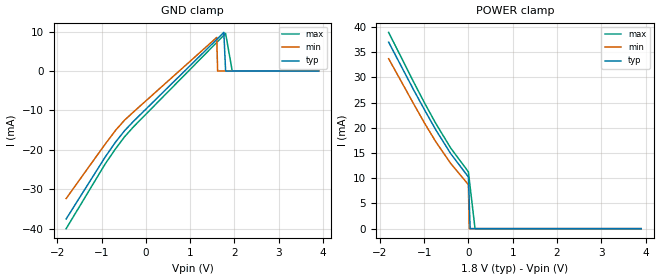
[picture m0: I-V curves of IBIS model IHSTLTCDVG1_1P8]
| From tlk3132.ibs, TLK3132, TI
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|   Model IHSTLTCDVG1_1P8
[Model]   IHSTLTCDVG1_1P8
Model_type   Input
Polarity   Non-Inverting
Vinl =   0.7000V
Vinh =   1.1000V
C_comp   0.7726pF   0.7726pF   0.7726pF
[Temperature Range]   25.0000   0.1250k   -40.0000
[Pullup Reference]   1.8000V   1.6200V   1.9500V
[Pulldown Reference]   0.000V   0.000V   0.000V
[POWER Clamp Reference]   1.8000V   1.6200V   1.9500V
[GND Clamp Reference]   0.000V   0.000V   0.000V
[GND_clamp]
| voltage   I(typ)   I(min)   I(max)
-1.8V     -37.52mA   -32.34mA   -39.98mA
-920mV    -21.83mA   -18.55mA   -23.58mA
-680mV    -17.94mA   -14.98mA   -19.65mA
-480mV    -15.12mA   -12.44mA   -16.66mA
-280mV    -12.76mA   -10.38mA   -14.15mA
1.6V      8.025mA    8.527mA    7.266mA
1.62V     8.248mA    0A         7.494mA
1.76V     9.803mA    0A         9.093mA
1.8V      0A         0A         9.55mA
1.95V     0A         0A         0A
3.9V      0A         0A         0A
[POWER_clamp]
| voltage   I(typ)   I(min)   I(max)
-1.8V     36.96mA    33.69mA    38.9mA
-1.24V    27.57mA    24.8mA     29.13mA
-980mV    23.39mA    20.77mA    24.76mA
-740mV    19.65mA    17.29mA    20.92mA
-400mV    14.88mA    12.93mA    15.99mA
0V        10.25mA    8.731mA    11.26mA
20mV      5.124mA    0A         9.761mA
40mV      0A         0A         8.26mA
150mV     0A         0A         0A
3.9V      0A         0A         0A
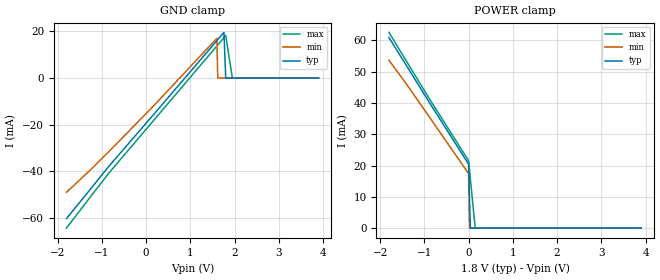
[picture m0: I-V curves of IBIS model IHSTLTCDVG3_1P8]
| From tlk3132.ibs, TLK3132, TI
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|   Model IHSTLTCDVG3_1P8
[Model]   IHSTLTCDVG3_1P8
Model_type   Input
Polarity   Non-Inverting
Vinl =   0.7000V
Vinh =   1.1000V
C_comp   0.7726pF   0.7726pF   0.7726pF
[Temperature Range]   25.0000   0.1250k   -40.0000
[Pullup Reference]   1.8000V   1.6200V   1.9500V
[Pulldown Reference]   0.000V   0.000V   0.000V
[POWER Clamp Reference]   1.8000V   1.6200V   1.9500V
[GND Clamp Reference]   0.000V   0.000V   0.000V
[GND_clamp]
| voltage   I(typ)   I(min)   I(max)
-1.8V     -60.18mA   -48.92mA   -64.26mA
-1.28V    -48.08mA   -39.71mA   -51.4mA
-840mV    -37.76mA   -31.45mA   -40.65mA
160mV     -15.83mA   -12.1mA    -18.36mA
1.6V      16.03mA    17.04mA    13.74mA
1.62V     16.48mA    0A         14.19mA
1.76V     19.58mA    0A         17.32mA
1.8V      0A         0A         18.21mA
1.95V     0A         0A         0A
3.9V      0A         0A         0A
[POWER_clamp]
| voltage   I(typ)   I(min)   I(max)
-1.8V     60.93mA    53.67mA    62.57mA
-1.42V    52.3mA     46.36mA    53.7mA
-880mV    40.01mA    35.39mA    41.21mA
0V        20.47mA    17.44mA    21.56mA
20mV      10.24mA    0A         18.69mA
40mV      0A         0A         15.81mA
150mV     0A         0A         0A
3.9V      0A         0A         0A
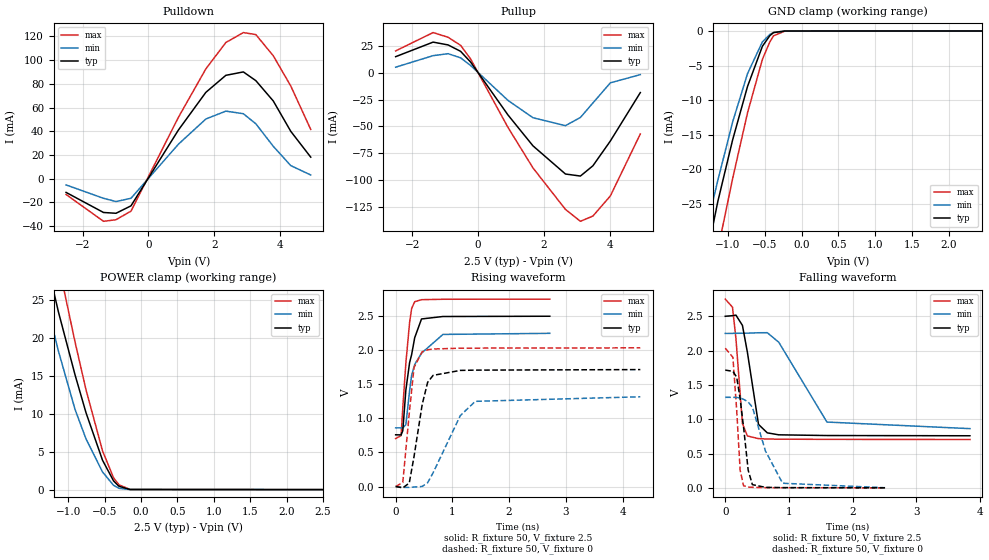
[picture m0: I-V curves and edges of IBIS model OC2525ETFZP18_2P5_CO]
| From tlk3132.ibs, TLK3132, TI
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[Model]   OC2525ETFZP18_2P5_CO
Model_type   3-state
Polarity   Non-Inverting
Enable   Active-Low
Cref =  15.0000pF
Rref =  100.0000M
Vref =  0V
Vmeas =  1.25
C_comp   2.165358p   2.063246p   2.20655p
[Temperature Range]   25   105   0
[Voltage Range]   2.5   2.25   2.75
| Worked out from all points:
|   slope of the pulldown table from 0 to 0.375 V, typ, clamps not added: 21.4 ohm
|   slope of the pullup table from 0 to 0.375 V, typ, clamps not added: 22.5 ohm
|   GND clamp passes 1 mA (typ) near -0.45 V on its own axis
|   POWER clamp passes 1 mA (typ) near -0.36 V on its own axis
|   rising waveform, R_fixture 50, V_fixture 2.5: 20-80 % time 176ps typ, 256ps min, 115ps max; typ from 0.759 V to 2.5 V
|   rising waveform, R_fixture 50, V_fixture 0: 20-80 % time 200ps typ, 450ps min, 129ps max; typ from 0 V to 1.72 V
|   falling waveform, R_fixture 50, V_fixture 2.5: 20-80 % time 169ps typ, 466ps min, 101ps max; typ from 2.5 V to 0.759 V
|   falling waveform, R_fixture 50, V_fixture 0: 20-80 % time 125ps typ, 283ps min, 75.3ps max; typ from 1.72 V to 0.001 V
[POWER_clamp]
|   voltage   I(typ)   I(min)   I(max)
-2.5V     96.31mA    74.55mA    118.9mA
-1.439V   37.03mA    30.25mA    45.49mA
-1.414V   35.75mA    29.22mA    44mA
-1.288V   29.62mA    24.09mA    36.98mA
-1.136V   23.36mA    18.21mA    29.68mA
-909.1mV  15.13mA    10.57mA    19.46mA
-757.6mV  10.12mA    6.678mA    13.14mA
-530.3mV  3.861mA    2.318mA    5.098mA
-378.8mV  1.145mA    563.9uA    1.555mA
-303mV    430uA      166.8uA    623.9uA
-151.5mV  13.11uA    4.632uA    27.06uA
2.5V      28.56nA    86.45nA    144.6nA
[Pulldown]
|   voltage   I(typ)   I(min)   I(max)
-2.5V     -11.51mA   -5.197mA   -13.25mA
-1.364V   -28.44mA   -16.49mA   -35.88mA
-984.8mV  -29.11mA   -19.22mA   -34.54mA
-530.3mV  -22.86mA   -16.47mA   -27.32mA
909.1mV   41.11mA    29.14mA    51.82mA
1.742V    72.89mA    50.39mA    92.67mA
2.348V    87.23mA    57.05mA    114.9mA
2.879V    90.11mA    54.86mA    123.3mA
3.258V    82.75mA    46.37mA    121.6mA
3.788V    65.59mA    27.35mA    103.7mA
4.318V    40.02mA    11.09mA    78.25mA
4.924V    18.22mA    3.193mA    41.59mA
[Pullup]
|   voltage   I(typ)   I(min)   I(max)
-2.5V     15.14mA    5.321mA    20.54mA
-1.364V   28.74mA    16.09mA    37.67mA
-909.1mV  26.12mA    17.93mA    33.28mA
-530.3mV  20.16mA    14.07mA    25.77mA
-227.3mV  10.18mA    6.927mA    13.07mA
909.1mV   -39.37mA   -25.74mA   -51mA
1.667V    -68.19mA   -41.92mA   -88.83mA
2.652V    -94.51mA   -49.32mA   -127.6mA
3.106V    -96.42mA   -41.68mA   -138.7mA
3.485V    -86.83mA   -28.14mA   -133.8mA
4.015V    -63.65mA   -9.296mA   -115mA
4.924V    -18.42mA   -1.643mA   -57.06mA
[GND_clamp]
|   voltage   I(typ)   I(min)   I(max)
-2.5V     -108.6mA   -85.04mA   -132.8mA
-1.338V   -35.83mA   -30.8mA    -43.73mA
-1.288V   -32.85mA   -28.48mA   -40.35mA
-1.237V   -30.02mA   -26.18mA   -37.34mA
-1.136V   -24.7mA    -21.65mA   -31.7mA
-934.3mV  -15.75mA   -13.16mA   -21.35mA
-732.3mV  -8.028mA   -6.171mA   -11.84mA
-530.3mV  -2.208mA   -1.574mA   -4.1mA
-429.3mV  -672.7uA   -500.5uA   -1.576mA
-378.8mV  -236.5uA   -196.8uA   -694.7uA
-227.3mV  -8.589uA   -10.62uA   -24.84uA
2.449V    -16.1nA    24.02uA    -49.99nA
[Ramp]
| variable   typ   min   max
dV/dt_f   1.058009/0.1680751n  0.8442659/0.4709843n   1.23621/0.1012939n
dV/dt_r   1.046172/0.2022347n  0.8097614/0.458531n   1.236612/0.1300444n
R_load = 50
[Rising Waveform]
R_fixture = 50
V_fixture = 2.5
V_fixture_min = 2.25
V_fixture_max = 2.75
|   time   V(typ)   V(min)   V(max)
0s        759mV      860.8mV    704.6mV
96ps      757.4mV    860.8mV    746.5mV
126ps     817.9mV    860.7mV    1.155V
180ps     1.416V     907.8mV    1.811V
246ps     1.818V     1.406V     2.407V
282ps     1.936V     1.633V     2.614V
336ps     2.184V     1.792V     2.712V
456ps     2.459V     1.956V     2.742V
834ps     2.495V     2.232V     2.748V
2.718ns   2.499V     2.248V     2.75V
[Rising Waveform]
R_fixture = 50
V_fixture = 0
V_fixture_min = 0
V_fixture_max = 0
|   time   V(typ)   V(min)   V(max)
0s        11.88uV    10.37uV    14.69uV
126ps     -19.66mV   -13.54mV   59.74mV
240ps     51.13mV    -13.27mV   1.074V
324ps     439.5mV    -7.069mV   1.748V
468ps     1.204V     1.241mV    1.978V
564ps     1.529V     55.1mV     2.006V
660ps     1.631V     200.3mV    2.018V
1.14ns    1.704V     1.041V     2.03V
1.404ns   1.708V     1.25V      2.031V
4.314ns   1.716V     1.317V     2.035V
[Falling Waveform]
R_fixture = 50
V_fixture = 2.5
V_fixture_min = 2.25
V_fixture_max = 2.75
|   time   V(typ)   V(min)   V(max)
0s        2.5V       2.25V      2.75V
114ps     2.509V     2.251V     2.633V
168ps     2.517V     2.252V     2.175V
270ps     2.367V     2.253V     935.2mV
348ps     1.974V     2.254V     756.7mV
522ps     924.7mV    2.26V      717.4mV
660ps     801.7mV    2.261V     711.8mV
840ps     773mV      2.122V     709.7mV
1.596ns   762.7mV    959mV      706.8mV
3.84ns    759.3mV    863.1mV    704.8mV
[Falling Waveform]
R_fixture = 50
V_fixture = 0
V_fixture_min = 0
V_fixture_max = 0
|   time   V(typ)   V(min)   V(max)
0s        1.716V     1.319V     2.036V
120ps     1.698V     1.319V     1.904V
180ps     1.612V     1.318V     1.127V
234ps     1.297V     1.309V     255.5mV
288ps     882.3mV    1.291V     30.95mV
360ps     258mV      1.25V      12.36mV
426ps     47.09mV    1.177V     8.519mV
630ps     7.865mV    540.2mV    3.581mV
900ps     3.864mV    67.55mV    1.839mV
2.508ns   1.021mV    2.274mV    269.2uV
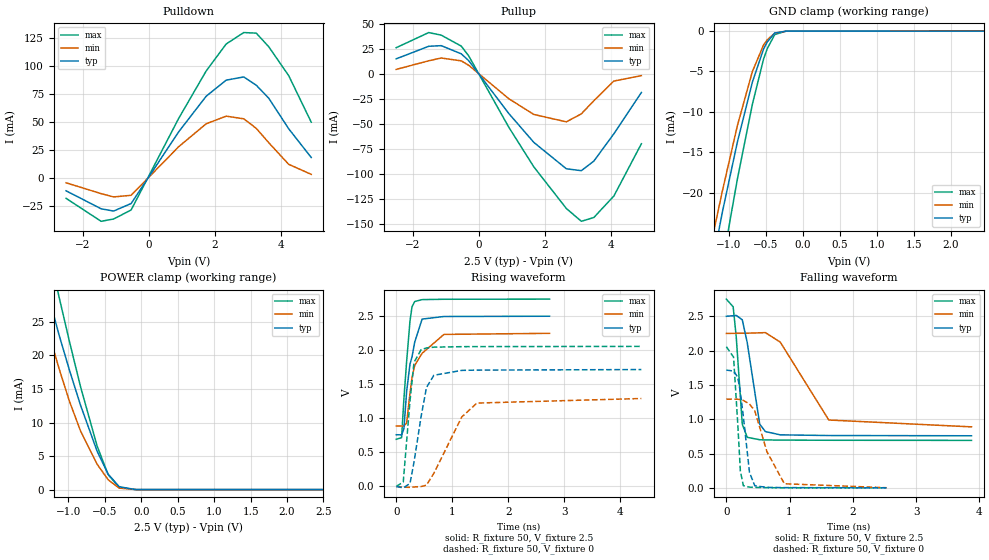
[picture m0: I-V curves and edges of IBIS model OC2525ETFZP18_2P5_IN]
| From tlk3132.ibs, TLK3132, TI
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|   Model Cell OC2525ETFZP18_2P5_IN
|OC2525ETFZP18_2P5
[Model]   OC2525ETFZP18_2P5_IN
Model_type   3-state
Polarity   Non-Inverting
Enable   Active-Low
Cref =  15.0000pF
Rref =  100.0000M
Vref =  0V
Vmeas =  1.25
C_comp   2.165358p   2.071537p   2.199857p
[Temperature Range]   25   125   -40
[Voltage Range]   2.5   2.25   2.75
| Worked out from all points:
|   slope of the pulldown table from 0 to 0.375 V, typ, clamps not added: 21.4 ohm
|   slope of the pullup table from 0 to 0.375 V, typ, clamps not added: 22.5 ohm
|   GND clamp passes 1 mA (typ) near -0.45 V on its own axis
|   POWER clamp passes 1 mA (typ) near -0.36 V on its own axis
|   rising waveform, R_fixture 50, V_fixture 2.5: 20-80 % time 177ps typ, 259ps min, 110ps max; typ from 0.759 V to 2.5 V
|   rising waveform, R_fixture 50, V_fixture 0: 20-80 % time 201ps typ, 467ps min, 118ps max; typ from 0 V to 1.72 V
|   falling waveform, R_fixture 50, V_fixture 2.5: 20-80 % time 169ps typ, 478ps min, 92.8ps max; typ from 2.5 V to 0.759 V
|   falling waveform, R_fixture 50, V_fixture 0: 20-80 % time 125ps typ, 284ps min, 72.6ps max; typ from 1.72 V to 0.001 V
[POWER_clamp]
|   voltage   I(typ)   I(min)   I(max)
-2.5V     96.31mA    72.13mA    116.7mA
-1.414V   35.75mA    28.89mA    42.74mA
-1.263V   28.53mA    23.04mA    35.14mA
-1.136V   23.36mA    18.34mA    29.09mA
-1.111V   22.41mA    17.44mA    27.91mA
-984.8mV  17.78mA    13.14mA    22.04mA
-833.3mV  12.57mA    8.738mA    15.33mA
-606.1mV  5.731mA    3.789mA    6.501mA
-454.5mV  2.303mA    1.469mA    2.233mA
-303mV    430uA      224.9uA    328.3uA
-75.76mV  1.002uA    1.068uA    314nA
2.5V      28.56nA    166.7nA    20.27nA
[Pulldown]
|   voltage   I(typ)   I(min)   I(max)
-2.5V     -11.51mA   -4.355mA   -18.23mA
-1.439V   -27.54mA   -14.02mA   -38.71mA
-1.061V   -29.58mA   -16.96mA   -36.67mA
-530.3mV  -22.86mA   -15.51mA   -28.6mA
909.1mV   41.11mA    27.83mA    53.08mA
1.742V    72.89mA    48.31mA    95.41mA
2.348V    87.24mA    55.11mA    119.5mA
2.879V    90.11mA    52.76mA    129.7mA
3.258V    82.75mA    44.24mA    129.2mA
3.636V    71.17mA    31.46mA    117.1mA
4.242V    43.83mA    12.12mA    91.23mA
4.924V    18.22mA    3.163mA    49.72mA
[Pullup]
|   voltage   I(typ)   I(min)   I(max)
-2.5V     15.14mA    4.579mA    26.25mA
-1.515V   27.67mA    13.2mA     41.34mA
-1.136V   28.28mA    15.97mA    38.76mA
-530.3mV  20.16mA    13.13mA    27.83mA
-303mV    13.29mA    8.656mA    17.98mA
909.1mV   -39.37mA   -24.63mA   -53.05mA
1.667V    -68.19mA   -40.33mA   -92.6mA
2.652V    -94.51mA   -47.7mA    -134.1mA
3.106V    -96.42mA   -39.76mA   -146.9mA
3.485V    -86.83mA   -26.62mA   -143.1mA
4.091V    -59.63mA   -7mA       -121.7mA
4.924V    -18.42mA   -1.634mA   -69.58mA
[GND_clamp]
|   voltage   I(typ)   I(min)   I(max)
-2.5V     -108.6mA   -82.37mA   -130.6mA
-1.338V   -35.83mA   -30.63mA   -42.43mA
-1.237V   -30.02mA   -26.21mA   -36.83mA
-1.136V   -24.7mA    -21.86mA   -31.39mA
-1.086V   -22.33mA   -19.73mA   -28.71mA
-883.8mV  -13.7mA    -11.67mA   -18.28mA
-681.8mV  -6.328mA   -5.01mA    -9.064mA
-530.3mV  -2.208mA   -1.716mA   -3.461mA
-479.8mV  -1.33mA    -1.072mA   -2.159mA
-378.8mV  -236.5uA   -245.3uA   -425.1uA
-227.3mV  -8.589uA   -14.97uA   -10.06uA
2.449V    -16.1nA    36.08uA    -11.59nA
[Ramp]
| variable   typ   min   max
dV/dt_f   1.058049/0.1679937n  0.8284366/0.4822911n   1.244699/93.65658p
dV/dt_r   1.046052/0.2029092n  0.7938531/0.4761418n   1.249486/0.1189967n
R_load = 50
[Rising Waveform]
R_fixture = 50
V_fixture = 2.5
V_fixture_min = 2.25
V_fixture_max = 2.75
|   time   V(typ)   V(min)   V(max)
0s        759mV      886.7mV    692.1mV
96ps      757.4mV    886.6mV    716.3mV
138ps     849mV      886.4mV    1.293V
186ps     1.395V     931.6mV    1.835V
246ps     1.796V     1.367V     2.431V
282ps     1.902V     1.599V     2.637V
330ps     2.118V     1.777V     2.715V
462ps     2.457V     1.955V     2.743V
852ps     2.495V     2.232V     2.748V
2.736ns   2.499V     2.248V     2.75V
[Rising Waveform]
R_fixture = 50
V_fixture = 0
V_fixture_min = 0
V_fixture_max = 0
|   time   V(typ)   V(min)   V(max)
0s        11.88uV    11.24uV    11.91uV
126ps     -20.83mV   -10.99mV   65.26mV
246ps     43.77mV    -13.37mV   1.258V
318ps     359.3mV    -7.766mV   1.822V
444ps     1.025V     -1.33mV    2.007V
540ps     1.453V     19.11mV    2.033V
672ps     1.632V     194.1mV    2.045V
1.17ns    1.704V     1.02V      2.052V
1.44ns    1.708V     1.224V     2.053V
4.374ns   1.716V     1.291V     2.056V
[Falling Waveform]
R_fixture = 50
V_fixture = 2.5
V_fixture_min = 2.25
V_fixture_max = 2.75
|   time   V(typ)   V(min)   V(max)
0s        2.5V       2.25V      2.75V
108ps     2.508V     2.251V     2.638V
156ps     2.513V     2.252V     2.207V
252ps     2.449V     2.253V     927.7mV
330ps     2.118V     2.254V     736.7mV
528ps     927.4mV    2.259V     701.3mV
618ps     820.3mV    2.262V     698.6mV
852ps     772.7mV    2.124V     696.2mV
1.62ns    762.7mV    988.9mV    693.7mV
3.876ns   759.2mV    888.9mV    692.1mV
[Falling Waveform]
R_fixture = 50
V_fixture = 0
V_fixture_min = 0
V_fixture_max = 0
|   time   V(typ)   V(min)   V(max)
0s        1.716V     1.293V     2.057V
114ps     1.702V     1.293V     1.906V
180ps     1.615V     1.292V     945.5mV
222ps     1.393V     1.286V     241.8mV
270ps     1.031V     1.273V     31.43mV
366ps     226.9mV    1.223V     10.71mV
450ps     29.86mV    1.123V     6.883mV
642ps     7.572mV    526.8mV    3.04mV
918ps     3.724mV    59.94mV    1.586mV
2.532ns   1.002mV    2.269mV    195.7uV
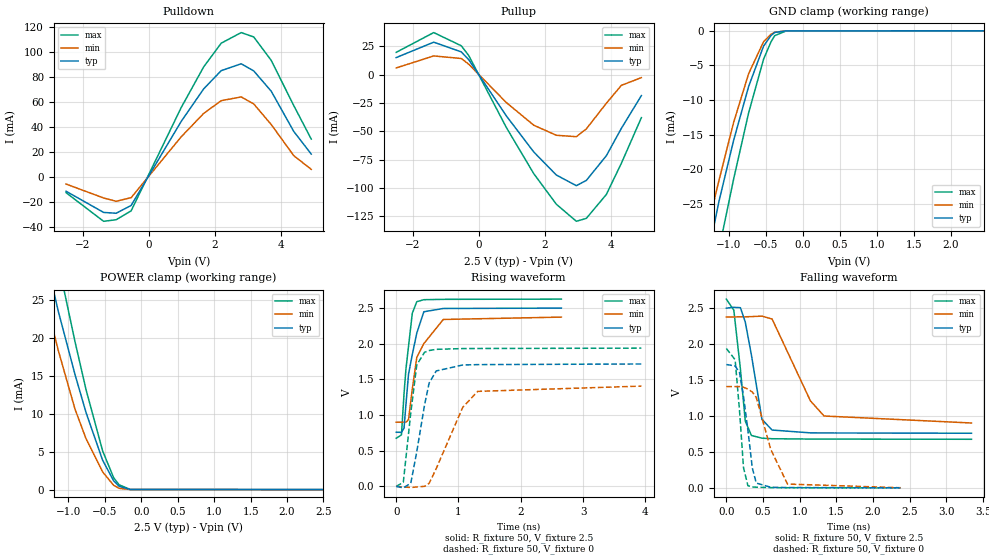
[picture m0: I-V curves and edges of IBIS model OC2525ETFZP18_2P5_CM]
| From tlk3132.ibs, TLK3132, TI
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|   Model Cell OC2525ETFZP18_2P5_CM
|OC2525ETFZP18_2P5
[Model]   OC2525ETFZP18_2P5_CM
Model_type   3-state
Polarity   Non-Inverting
Enable   Active-Low
Cref =  15.0000pF
Rref =  100.0000M
Vref =  0V
Vmeas =  1.25
C_comp   2.165358p   2.063246p   2.20655p
[Temperature Range]   25   105   0
[Voltage Range]   2.5   2.375   2.625
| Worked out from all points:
|   slope of the pulldown table from 0 to 0.375 V, typ, clamps not added: 21.4 ohm
|   slope of the pullup table from 0 to 0.375 V, typ, clamps not added: 22.5 ohm
|   GND clamp passes 1 mA (typ) near -0.45 V on its own axis
|   POWER clamp passes 1 mA (typ) near -0.36 V on its own axis
|   rising waveform, R_fixture 50, V_fixture 2.5: 20-80 % time 178ps typ, 254ps min, 120ps max; typ from 0.759 V to 2.5 V
|   rising waveform, R_fixture 50, V_fixture 0: 20-80 % time 202ps typ, 422ps min, 135ps max; typ from 0 V to 1.72 V
|   falling waveform, R_fixture 50, V_fixture 2.5: 20-80 % time 167ps typ, 374ps min, 109ps max; typ from 2.5 V to 0.76 V
|   falling waveform, R_fixture 50, V_fixture 0: 20-80 % time 125ps typ, 246ps min, 80.8ps max; typ from 1.72 V to 0.001 V
[POWER_clamp]
|   voltage   I(typ)   I(min)   I(max)
-2.5V     96.31mA    74.49mA    119mA
-1.439V   37.03mA    30.24mA    45.5mA
-1.414V   35.75mA    29.21mA    44.01mA
-1.288V   29.62mA    24.08mA    36.97mA
-1.136V   23.36mA    18.21mA    29.67mA
-909.1mV  15.13mA    10.58mA    19.45mA
-757.6mV  10.12mA    6.687mA    13.13mA
-530.3mV  3.861mA    2.321mA    5.096mA
-378.8mV  1.145mA    564.3uA    1.555mA
-303mV    430uA      166.9uA    623.8uA
-151.5mV  13.11uA    4.636uA    27.05uA
2.5V      28.56nA    90.38nA    134.4nA
[Pulldown]
|   voltage   I(typ)   I(min)   I(max)
-2.5V     -11.51mA   -5.753mA   -12.66mA
-1.364V   -28.44mA   -16.89mA   -35.54mA
-984.8mV  -29.11mA   -19.52mA   -34.29mA
-530.3mV  -22.86mA   -16.64mA   -27.18mA
984.8mV   44.29mA    31.99mA    55.37mA
1.667V    70.38mA    50.75mA    87.97mA
2.197V    84.93mA    60.93mA    106.9mA
2.803V    90.44mA    63.93mA    115.4mA
3.182V    84.75mA    58.34mA    111.9mA
3.712V    68.51mA    41.86mA    93.15mA
4.394V    36.35mA    16.97mA    57.06mA
4.924V    18.22mA    6.004mA    30.2mA
[Pullup]
|   voltage   I(typ)   I(min)   I(max)
-2.5V     15.14mA    5.995mA    19.77mA
-1.364V   28.74mA    16.61mA    37.21mA
-530.3mV  20.16mA    14.32mA    25.57mA
-303mV    13.29mA    9.29mA     16.92mA
833.3mV   -36.25mA   -24.5mA    -46.44mA
1.667V    -68.19mA   -44.56mA   -87.35mA
2.348V    -88.45mA   -53.4mA    -114.2mA
2.955V    -97.88mA   -54.64mA   -129.3mA
3.258V    -93.21mA   -47.75mA   -126.7mA
3.864V    -71.43mA   -25.16mA   -105.6mA
4.318V    -47.32mA   -9.363mA   -78.14mA
4.924V    -18.42mA   -2.545mA   -37.89mA
[GND_clamp]
|   voltage   I(typ)   I(min)   I(max)
-2.5V     -108.6mA   -85.04mA   -132.8mA
-1.338V   -35.83mA   -30.81mA   -43.71mA
-1.288V   -32.85mA   -28.48mA   -40.33mA
-1.237V   -30.02mA   -26.19mA   -37.31mA
-1.136V   -24.7mA    -21.66mA   -31.68mA
-934.3mV  -15.75mA   -13.17mA   -21.33mA
-732.3mV  -8.028mA   -6.178mA   -11.83mA
-530.3mV  -2.208mA   -1.576mA   -4.096mA
-429.3mV  -672.7uA   -501uA     -1.574mA
-378.8mV  -236.5uA   -197.1uA   -693.9uA
-227.3mV  -8.589uA   -10.84uA   -24.55uA
2.449V    -16.09nA   934.2nA    -11.05nA
[Ramp]
| variable   typ   min   max
dV/dt_f   1.058102/0.1678686n  0.8966017/0.3769081n   1.179026/0.1098508n
dV/dt_r   1.045805/0.2043142n  0.8618929/0.4272982n   1.179548/0.1368187n
R_load = 50
[Rising Waveform]
R_fixture = 50
V_fixture = 2.5
V_fixture_min = 2.375
V_fixture_max = 2.625
|   time   V(typ)   V(min)   V(max)
0s        759mV      900mV      675.3mV
84ps      757.9mV    899.9mV    721.6mV
126ps     817.6mV    900mV      1.304V
156ps     1.145V     899.2mV    1.643V
198ps     1.574V     937mV      1.965V
258ps     1.847V     1.361V     2.426V
330ps     2.148V     1.808V     2.589V
444ps     2.448V     2.002V     2.617V
756ps     2.494V     2.34V      2.622V
2.652ns   2.499V     2.373V     2.625V
[Rising Waveform]
R_fixture = 50
V_fixture = 0
V_fixture_min = 0
V_fixture_max = 0
|   time   V(typ)   V(min)   V(max)
0s        11.88uV    11.01uV    13.95uV
114ps     -20.4mV    -6.877mV   57.76mV
234ps     44.01mV    -15.83mV   1.032V
330ps     485.3mV    -7.753mV   1.703V
456ps     1.146V     1.347mV    1.88V
528ps     1.447V     41.75mV    1.904V
642ps     1.618V     248.6mV    1.921V
1.068ns   1.702V     1.108V     1.932V
1.308ns   1.707V     1.332V     1.933V
3.936ns   1.716V     1.406V     1.938V
[Falling Waveform]
R_fixture = 50
V_fixture = 2.5
V_fixture_min = 2.375
V_fixture_max = 2.625
|   time   V(typ)   V(min)   V(max)
0s        2.5V       2.375V     2.625V
102ps     2.511V     2.377V     2.472V
192ps     2.506V     2.379V     1.652V
258ps     2.307V     2.379V     929.9mV
342ps     1.848V     2.382V     729mV
486ps     952.2mV    2.389V     691.6mV
624ps     804.4mV    2.348V     683.5mV
1.146ns   765.1mV    1.211V     679mV
1.332ns   763.8mV    999.6mV    678.4mV
3.342ns   759.7mV    902.4mV    676mV
[Falling Waveform]
R_fixture = 50
V_fixture = 0
V_fixture_min = 0
V_fixture_max = 0
|   time   V(typ)   V(min)   V(max)
0s        1.716V     1.409V     1.939V
120ps     1.696V     1.409V     1.782V
180ps     1.602V     1.409V     1.073V
234ps     1.273V     1.399V     282.1mV
294ps     804.2mV    1.375V     30.17mV
354ps     278.4mV    1.333V     12.96mV
408ps     67.11mV    1.258V     9.338mV
606ps     8.462mV    533.5mV    3.973mV
834ps     4.514mV    53.03mV    2.035mV
2.376ns   1.134mV    2.399mV    311.7uV
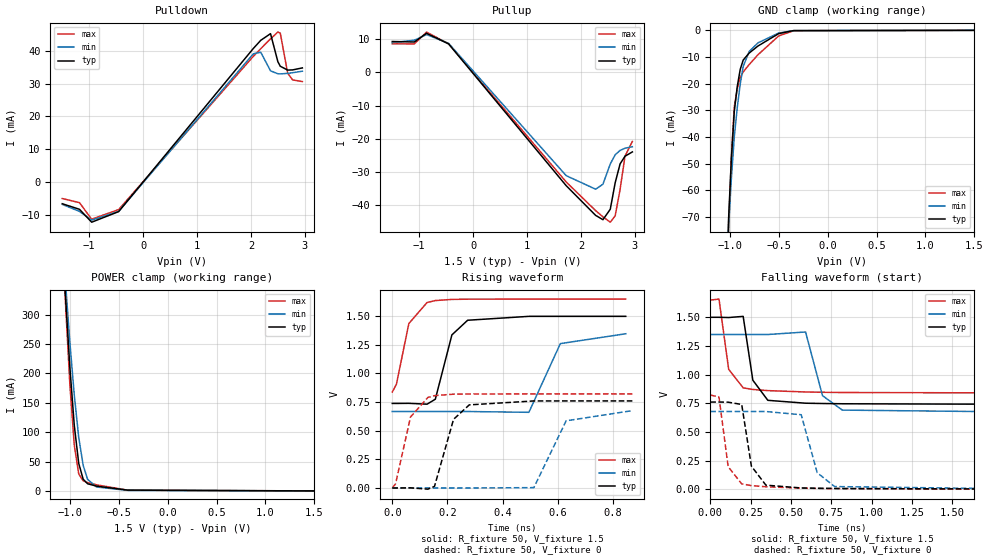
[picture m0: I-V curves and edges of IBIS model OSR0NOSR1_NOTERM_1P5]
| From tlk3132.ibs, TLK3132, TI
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|   Model Cell OSR0NOSR1_NOTERM_1P5
|NOSR0NOSR1_NOTERM_1P5
[Model]   OSR0NOSR1_NOTERM_1P5
Model_type   3-state
Polarity   Non-Inverting
Enable   Active-Low
Cref =  15.0000pF
Rref =  100.0000M
Vref =  0V
Vmeas =  0.75
C_comp   1.311337p   1.240052p   1.381049p
[Temperature Range]   25   125   -40
[Voltage Range]   1.5   1.35   1.65
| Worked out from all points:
|   slope of the pulldown table from 0 to 0.225 V, typ, clamps not added: 48.2 ohm
|   slope of the pullup table from 0 to 0.225 V, typ, clamps not added: 48 ohm
|   GND clamp passes 1 mA (typ) near -0.48 V on its own axis
|   POWER clamp passes 1 mA (typ) near -0.38 V on its own axis
|   rising waveform, R_fixture 50, V_fixture 1.5: 20-80 % time 51.2ps typ, 58.7ps min, 47.4ps max; typ from 0.739 V to 1.5 V
|   rising waveform, R_fixture 50, V_fixture 0: 20-80 % time 54.7ps typ, 70ps min, 50.2ps max; typ from 0 V to 0.76 V
|   falling waveform, R_fixture 50, V_fixture 1.5: 20-80 % time 55ps typ, 67.8ps min, 52.3ps max; typ from 1.5 V to 0.74 V
|   falling waveform, R_fixture 50, V_fixture 0: 20-80 % time 53.3ps typ, 70.3ps min, 50.7ps max; typ from 0.761 V to 0.002 V
[POWER_clamp]
|   voltage   I(typ)   I(min)   I(max)
-1.5V     1.852A     1.601A     2.096A
-1.061V   377.6mA    392.9mA    374mA
-1.045V   332.8mA    356mA      321.5mA
-1.03V    292.2mA    321.8mA    275mA
-1V       211mA      253.4mA    181.9mA
-954.5mV  111.3mA    163mA      77.64mA
-909.1mV  46.83mA    91.01mA    28.92mA
-863.6mV  19.88mA    43.45mA    17.23mA
-818.2mV  12.16mA    19.6mA     14.12mA
-727.3mV  8.165mA    6.726mA    10.4mA
-409.1mV  1.376mA    880.6uA    1.274mA
1.5V      14.89nA    105.6nA    8.857nA
[Pulldown]
|   voltage   I(typ)   I(min)   I(max)
-1.5V     -6.667mA   -6.872mA   -5.079mA
-1.182V   -8.366mA   -9.005mA   -6.333mA
-954.5mV  -12.31mA   -11.68mA   -11.4mA
-454.5mV  -9.078mA   -8.982mA   -8.456mA
2.045V    40.79mA    39.16mA    38.4mA
2.182V    43.27mA    39.66mA    40.71mA
2.364V    45.32mA    33.96mA    43.74mA
2.5V      36.76mA    33.06mA    45.8mA
2.545V    35.36mA    33.02mA    45.49mA
2.682V    34.18mA    33.18mA    33.26mA
2.773V    34.24mA    33.38mA    31.19mA
2.955V    34.85mA    33.84mA    30.67mA
[Pullup]
|   voltage   I(typ)   I(min)   I(max)
-1.5V     9.208mA    8.869mA    8.526mA
-1.091V   9.066mA    9.604mA    8.486mA
-863.6mV  11.68mA    11.3mA     12.04mA
-454.5mV  8.493mA    8.644mA    8.504mA
1.727V    -34.07mA   -31.06mA   -32.95mA
2.273V    -42.98mA   -35.12mA   -41.55mA
2.409V    -44.28mA   -33.62mA   -43.43mA
2.545V    -41.14mA   -27.54mA   -45.03mA
2.636V    -33.19mA   -24.8mA    -43.12mA
2.727V    -27.53mA   -23.48mA   -35.21mA
2.818V    -25.23mA   -22.82mA   -25.22mA
2.955V    -23.93mA   -22.38mA   -20.79mA
[GND_clamp]
|   voltage   I(typ)   I(min)   I(max)
-1.5V     -1.99A     -1.518A    -2.426A
-1.015V   -72.36mA   -74.91mA   -76.76mA
-984.8mV  -48.51mA   -55.8mA    -47.87mA
-954.5mV  -30.42mA   -39.97mA   -28.58mA
-924.2mV  -21.06mA   -28.95mA   -21.99mA
-893.9mV  -14.64mA   -20.14mA   -17.66mA
-863.6mV  -11.15mA   -13.54mA   -15.57mA
-803mV    -8.521mA   -7.949mA   -12.86mA
-712.1mV  -5.867mA   -4.684mA   -9.137mA
-500mV    -1.209mA   -994.1uA   -2.074mA
-348.5mV  -89.2uA    -110.3uA   -156.7uA
1.5V      14.89nA    6.861uA    -6.796nA
[Ramp]
| variable   typ   min   max
dV/dt_f  0.4694076/54.30025p   0.4228088/66.41315p   0.4960231/52.30563p
dV/dt_r  0.4660452/54.62114p   0.418309/70.65779p   0.5005426/50.08884p
R_load = 50
[Rising Waveform]
R_fixture = 50
V_fixture = 1.5
V_fixture_min = 1.35
V_fixture_max = 1.65
|   time   V(typ)   V(min)   V(max)
0s        738.5mV    668mV      838.2mV
15ps      738.4mV    668mV      906.4mV
60ps      739.4mV    668mV      1.436V
126ps     732mV      668mV      1.62V
156ps     775.5mV    668mV      1.637V
216ps     1.337V     668mV      1.647V
273ps     1.465V     668mV      1.649V
495ps     1.499V     660.9mV    1.65V
609ps     1.499V     1.261V     1.65V
846ps     1.499V     1.347V     1.65V
[Rising Waveform]
R_fixture = 50
V_fixture = 0
V_fixture_min = 0
V_fixture_max = 0
|   time   V(typ)   V(min)   V(max)
0s        43.28uV    35.23uV    48.88uV
12ps      -70.87uV   35.19uV    37.01mV
66ps      1.344mV    35.04uV    619.9mV
129ps     -10.25mV   35.66uV    790.6mV
153ps     14.23mV    37.16uV    806.4mV
222ps     599.8mV    27.69uV    819.4mV
279ps     725.9mV    -70.06uV   821mV
513ps     760.2mV    3.248mV    821.6mV
630ps     760.4mV    586.7mV    821.7mV
870ps     760.4mV    675.8mV    821.9mV
[Falling Waveform]
R_fixture = 50
V_fixture = 1.5
V_fixture_min = 1.35
V_fixture_max = 1.65
|   time   V(typ)   V(min)   V(max)
0s        1.5V       1.35V      1.65V
54ps      1.5V       1.35V      1.659V
114ps     1.498V     1.35V      1.047V
204ps     1.508V     1.35V      885mV
264ps     951.5mV    1.35V      870.7mV
357ps     776.1mV    1.35V      860.8mV
591ps     751mV      1.372V     848.9mV
696ps     748.4mV    816.9mV    846.3mV
819ps     746.2mV    690.9mV    844.3mV
2.178ns   740.5mV    670.7mV    839.7mV
[Falling Waveform]
R_fixture = 50
V_fixture = 0
V_fixture_min = 0
V_fixture_max = 0
|   time   V(typ)   V(min)   V(max)
0s        760.9mV    678.6mV    822.1mV
54ps      761mV      678.6mV    805mV
111ps     760mV      678.6mV    197mV
195ps     739.8mV    678.6mV    47.84mV
255ps     202.2mV    678.6mV    32.49mV
345ps     36.46mV    678.6mV    22.29mV
564ps     12.13mV    650.5mV    10.45mV
663ps     9.526mV    145.5mV    7.869mV
771ps     7.549mV    24.28mV    6.01mV
1.965ns   2.012mV    2.746mV    1.546mV
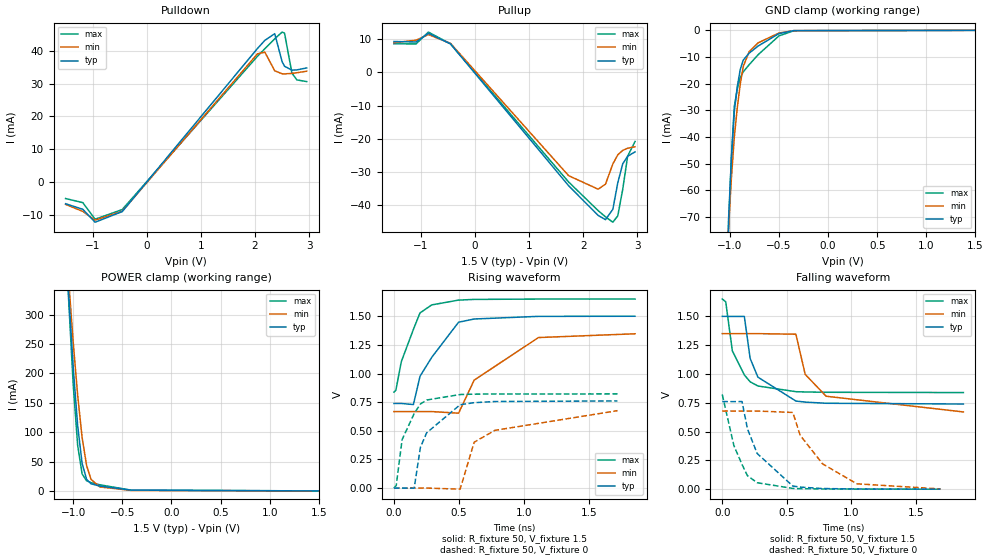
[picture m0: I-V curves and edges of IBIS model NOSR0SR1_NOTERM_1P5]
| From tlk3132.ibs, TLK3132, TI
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|   Model Cell NOSR0SR1_NOTERM_1P5
|NOSR0SR1_NOTERM_1P5
[Model]   NOSR0SR1_NOTERM_1P5
Model_type   3-state
Polarity   Non-Inverting
Enable   Active-Low
Cref =  15.0000pF
Rref =  100.0000M
Vref =  0V
Vmeas =  0.75
C_comp   1.311337p   1.240052p   1.381049p
[Temperature Range]   25   125   -40
[Voltage Range]   1.5   1.35   1.65
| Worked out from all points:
|   slope of the pulldown table from 0 to 0.225 V, typ, clamps not added: 48.2 ohm
|   slope of the pullup table from 0 to 0.225 V, typ, clamps not added: 48 ohm
|   GND clamp passes 1 mA (typ) near -0.48 V on its own axis
|   POWER clamp passes 1 mA (typ) near -0.38 V on its own axis
|   rising waveform, R_fixture 50, V_fixture 1.5: 20-80 % time 229ps typ, 456ps min, 146ps max; typ from 0.739 V to 1.5 V
|   rising waveform, R_fixture 50, V_fixture 0: 20-80 % time 180ps typ, 335ps min, 128ps max; typ from 0 V to 0.761 V
|   falling waveform, R_fixture 50, V_fixture 1.5: 20-80 % time 154ps typ, 204ps min, 127ps max; typ from 1.5 V to 0.739 V
|   falling waveform, R_fixture 50, V_fixture 0: 20-80 % time 200ps typ, 366ps min, 140ps max; typ from 0.761 V to 0.001 V
[POWER_clamp]
|   voltage   I(typ)   I(min)   I(max)
-1.5V     1.852A     1.601A     2.096A
-1.061V   377.6mA    392.9mA    374mA
-1.045V   332.8mA    356mA      321.5mA
-1.03V    292.2mA    321.8mA    275mA
-1V       211mA      253.4mA    181.9mA
-954.5mV  111.3mA    163mA      77.64mA
-909.1mV  46.83mA    91.01mA    28.92mA
-863.6mV  19.88mA    43.45mA    17.23mA
-818.2mV  12.16mA    19.6mA     14.12mA
-727.3mV  8.165mA    6.726mA    10.4mA
-409.1mV  1.376mA    880.6uA    1.274mA
1.5V      14.89nA    105.6nA    8.857nA
[Pulldown]
|   voltage   I(typ)   I(min)   I(max)
-1.5V     -6.667mA   -6.872mA   -5.079mA
-1.182V   -8.366mA   -9.005mA   -6.333mA
-954.5mV  -12.31mA   -11.68mA   -11.4mA
-454.5mV  -9.078mA   -8.982mA   -8.456mA
2.045V    40.79mA    39.16mA    38.4mA
2.182V    43.27mA    39.66mA    40.71mA
2.364V    45.32mA    33.96mA    43.74mA
2.5V      36.76mA    33.06mA    45.8mA
2.545V    35.36mA    33.02mA    45.49mA
2.682V    34.18mA    33.18mA    33.26mA
2.773V    34.24mA    33.38mA    31.19mA
2.955V    34.85mA    33.84mA    30.67mA
[Pullup]
|   voltage   I(typ)   I(min)   I(max)
-1.5V     9.208mA    8.869mA    8.526mA
-1.091V   9.066mA    9.604mA    8.486mA
-863.6mV  11.68mA    11.3mA     12.04mA
-454.5mV  8.493mA    8.644mA    8.504mA
1.727V    -34.07mA   -31.06mA   -32.95mA
2.273V    -42.98mA   -35.12mA   -41.55mA
2.409V    -44.28mA   -33.62mA   -43.43mA
2.545V    -41.14mA   -27.54mA   -45.03mA
2.636V    -33.19mA   -24.8mA    -43.12mA
2.727V    -27.53mA   -23.48mA   -35.21mA
2.818V    -25.23mA   -22.82mA   -25.22mA
2.955V    -23.93mA   -22.38mA   -20.79mA
[GND_clamp]
|   voltage   I(typ)   I(min)   I(max)
-1.5V     -1.99A     -1.518A    -2.426A
-1.015V   -72.36mA   -74.91mA   -76.76mA
-984.8mV  -48.51mA   -55.8mA    -47.87mA
-954.5mV  -30.42mA   -39.97mA   -28.58mA
-924.2mV  -21.06mA   -28.95mA   -21.99mA
-893.9mV  -14.64mA   -20.14mA   -17.66mA
-863.6mV  -11.15mA   -13.54mA   -15.57mA
-803mV    -8.521mA   -7.949mA   -12.86mA
-712.1mV  -5.867mA   -4.684mA   -9.137mA
-500mV    -1.209mA   -994.1uA   -2.074mA
-348.5mV  -89.2uA    -110.3uA   -156.7uA
1.5V      14.89nA    6.861uA    -6.796nA
[Ramp]
| variable   typ   min   max
dV/dt_f  0.4636529/0.1522151n  0.4154072/0.2044896n   0.492204/0.1265601n
dV/dt_r   0.464243/0.17724n   0.4163059/0.335681n   0.4990203/0.1280416n
R_load = 50
[Rising Waveform]
R_fixture = 50
V_fixture = 1.5
V_fixture_min = 1.35
V_fixture_max = 1.65
|   time   V(typ)   V(min)   V(max)
0s        738.5mV    668mV      838.2mV
15ps      738.5mV    668mV      854mV
57ps      738.8mV    668mV      1.104V
150ps     729mV      668mV      1.385V
201ps     975.7mV    668mV      1.529V
291ps     1.141V     668mV      1.599V
498ps     1.448V     653.7mV    1.641V
618ps     1.476V     942.3mV    1.647V
1.113ns   1.499V     1.314V     1.65V
1.857ns   1.5V       1.347V     1.65V
[Rising Waveform]
R_fixture = 50
V_fixture = 0
V_fixture_min = 0
V_fixture_max = 0
|   time   V(typ)   V(min)   V(max)
0s        43.28uV    35.23uV    48.88uV
18ps      -14.04uV   35.19uV    23.48mV
63ps      400.5uV    35.04uV    422.6mV
156ps     -796.1uV   36.51uV    650.7mV
204ps     355.8mV    39.56uV    733.6mV
252ps     482.4mV    -12.29uV   768.8mV
510ps     727.8mV    -9.455mV   816.7mV
618ps     745.4mV    400.4mV    820mV
777ps     755.7mV    503.7mV    821.5mV
1.722ns   760.8mV    675.9mV    822.1mV
[Falling Waveform]
R_fixture = 50
V_fixture = 1.5
V_fixture_min = 1.35
V_fixture_max = 1.65
|   time   V(typ)   V(min)   V(max)
0s        1.5V       1.35V      1.65V
27ps      1.5V       1.35V      1.626V
78ps      1.499V     1.35V      1.201V
171ps     1.499V     1.35V      991.9mV
216ps     1.134V     1.35V      932mV
276ps     972.5mV    1.35V      895.8mV
570ps     765.2mV    1.345V     846.5mV
642ps     756.1mV    996.2mV    843.9mV
804ps     746mV      806.9mV    841.2mV
1.866ns   739.4mV    670.7mV    838.8mV
[Falling Waveform]
R_fixture = 50
V_fixture = 0
V_fixture_min = 0
V_fixture_max = 0
|   time   V(typ)   V(min)   V(max)
0s        760.9mV    678.6mV    822.1mV
90ps      760.1mV    678.6mV    378.3mV
153ps     760.8mV    678.6mV    215.1mV
195ps     524.3mV    678.6mV    117.9mV
270ps     310.5mV    678.6mV    56.76mV
546ps     27.87mV    666.2mV    7.015mV
603ps     18.49mV    468.1mV    5.135mV
777ps     6.196mV    219.7mV    2.558mV
1.041ns   2.203mV    47.19mV    1.358mV
1.689ns   929.7uV    2.767mV    665.9uV
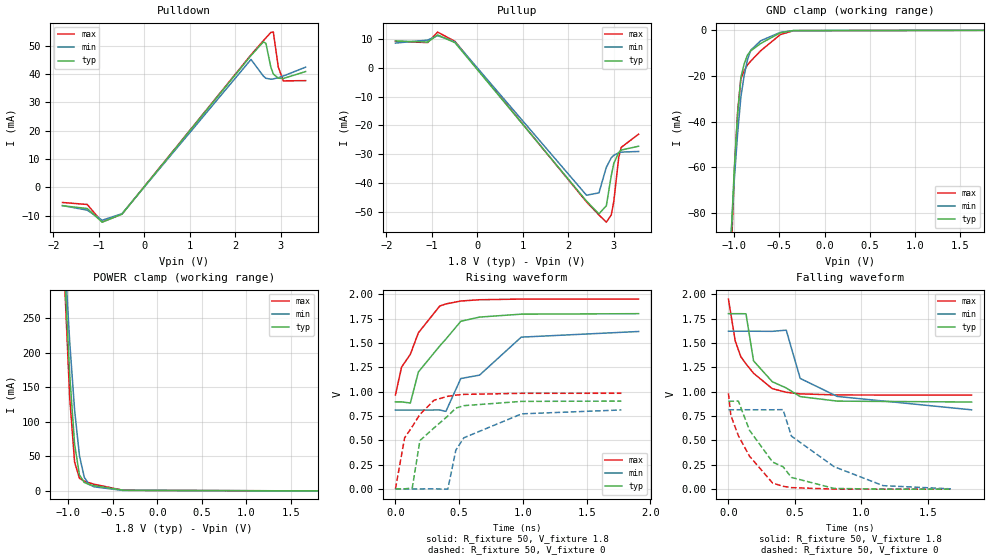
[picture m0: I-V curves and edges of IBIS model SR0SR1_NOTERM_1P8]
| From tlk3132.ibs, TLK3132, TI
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|   Model Cell SR0SR1_NOTERM_1P8
|SR0SR1_NOTERM_1P8
[Model]   SR0SR1_NOTERM_1P8
Model_type   3-state
Polarity   Non-Inverting
Enable   Active-Low
Cref =  15.0000pF
Rref =  100.0000M
Vref =  0V
Vmeas =  0.9
C_comp   1.295933p   1.227743p   1.363512p
[Temperature Range]   25   125   -40
[Voltage Range]   1.8   1.62   1.95
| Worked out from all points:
|   slope of the pulldown table from 0 to 0.27 V, typ, clamps not added: 49.1 ohm
|   slope of the pullup table from 0 to 0.27 V, typ, clamps not added: 49.3 ohm
|   GND clamp passes 1 mA (typ) near -0.48 V on its own axis
|   POWER clamp passes 1 mA (typ) near -0.38 V on its own axis
|   rising waveform, R_fixture 50, V_fixture 1.8: 20-80 % time 273ps typ, 467ps min, 192ps max; typ from 0.894 V to 1.8 V
|   rising waveform, R_fixture 50, V_fixture 0: 20-80 % time 227ps typ, 352ps min, 172ps max; typ from 0 V to 0.902 V
|   falling waveform, R_fixture 50, V_fixture 1.8: 20-80 % time 209ps typ, 309ps min, 188ps max; typ from 1.8 V to 0.894 V
|   falling waveform, R_fixture 50, V_fixture 0: 20-80 % time 317ps typ, 582ps min, 215ps max; typ from 0.902 V to 0 V
[POWER_clamp]
|   voltage   I(typ)   I(min)   I(max)
-1.8V     2.923A     2.485A     3.339A
-1.055V   360.5mA    378.7mA    354.2mA
-1.036V   307.2mA    334.7mA    291.8mA
-1.018V   260.7mA    295mA      239.4mA
-981.8mV  167.8mA    215.5mA    134.5mA
-927.3mV  67.68mA    117.2mA    41.81mA
-872.7mV  23.04mA    50.89mA    18.36mA
-818.2mV  12.16mA    19.6mA     14.12mA
-763.6mV  9.299mA    9.245mA    11.81mA
-709.1mV  7.658mA    5.964mA    9.714mA
-381.8mV  1.047mA    648.8uA    918.9uA
1.8V      20.41nA    122.3nA    26.44nA
[Pulldown]
|   voltage   I(typ)   I(min)   I(max)
-1.8V     -6.451mA   -6.405mA   -5.315mA
-1.255V   -7.43mA    -8.011mA   -6.013mA
-927.3mV  -12.26mA   -11.57mA   -12.21mA
-490.9mV  -9.427mA   -9.263mA   -9.389mA
2.345V    46.47mA    45.11mA    46.73mA
2.618V    51.3mA     39.22mA    51.73mA
2.673V    50.78mA    38.48mA    52.72mA
2.782V    42.33mA    38.14mA    54.63mA
2.836V    39.97mA    38.24mA    54.75mA
2.945V    38.49mA    38.68mA    42.44mA
3.055V    38.4mA     39.27mA    37.55mA
3.545V    40.84mA    42.38mA    37.64mA
[Pullup]
|   voltage   I(typ)   I(min)   I(max)
-1.8V     9.309mA    8.565mA    9.187mA
-1.091V   8.918mA    9.616mA    8.735mA
-872.7mV  11.39mA    11.15mA    12.38mA
-490.9mV  8.699mA    8.982mA    9.152mA
2.4V      -46.25mA   -44.22mA   -46.54mA
2.673V    -50.7mA    -43.41mA   -51.05mA
2.836V    -47.86mA   -34.53mA   -53.58mA
2.945V    -37.39mA   -31.21mA   -51.04mA
3V        -33.19mA   -30.38mA   -46.39mA
3.109V    -29.38mA   -29.49mA   -31.06mA
3.164V    -28.54mA   -29.26mA   -27.61mA
3.545V    -27.23mA   -29.05mA   -23.05mA
[GND_clamp]
|   voltage   I(typ)   I(min)   I(max)
-1.8V     -3.608A    -2.847A    -4.283A
-1.036V   -91.2mA    -89.54mA   -100.6mA
-1V       -60.4mA    -65.35mA   -62.23mA
-963.6mV  -36.87mA   -45.25mA   -35.78mA
-927.3mV  -20.6mA    -29.23mA   -21.19mA
-890.9mV  -14.74mA   -19.77mA   -17.76mA
-854.5mV  -10.87mA   -12.93mA   -15.19mA
-818.2mV  -9.005mA   -8.715mA   -13.5mA
-709.1mV  -5.779mA   -4.59mA    -9.01mA
-490.9mV  -1.081mA   -898uA     -1.867mA
-345.5mV  -89.76uA   -109.3uA   -157uA
1.764V    -18.75nA   7.297uA    -4.706nA
[Ramp]
| variable   typ   min   max
dV/dt_f  0.5507077/0.2057085n  0.4929198/0.3083154n  0.5965207/0.1868124n
dV/dt_r  0.5489608/0.2237207n  0.4987855/0.3508697n  0.5952604/0.1727053n
R_load = 50
[Rising Waveform]
R_fixture = 50
V_fixture = 1.8
V_fixture_min = 1.62
V_fixture_max = 1.95
|   time   V(typ)   V(min)   V(max)
0s        893.9mV    810.6mV    964.8mV
48ps      894.3mV    810.6mV    1.251V
117ps     882.4mV    810.6mV    1.383V
180ps     1.201V     810.6mV    1.604V
348ps     1.469V     811mV      1.879V
396ps     1.539V     796.9mV    1.9V
513ps     1.722V     1.134V     1.93V
660ps     1.765V     1.169V     1.943V
987ps     1.795V     1.559V     1.95V
1.908ns   1.8V       1.617V     1.95V
[Rising Waveform]
R_fixture = 50
V_fixture = 0
V_fixture_min = 0
V_fixture_max = 0
|   time   V(typ)   V(min)   V(max)
0s        57.94uV    48.16uV    61.33uV
72ps      1.208mV    47.87uV    524.6mV
132ps     10.08mV    48.72uV    640.5mV
192ps     496.9mV    48.79uV    765.9mV
303ps     627mV      978.9uV    911.5mV
411ps     749.4mV    -1.991mV   951.7mV
474ps     829.9mV    399.2mV    963.8mV
537ps     855.5mV    525.5mV    971.1mV
990ps     899.4mV    771.3mV    982.3mV
1.773ns   902.2mV    811.4mV    982.6mV
[Falling Waveform]
R_fixture = 50
V_fixture = 1.8
V_fixture_min = 1.62
V_fixture_max = 1.95
|   time   V(typ)   V(min)   V(max)
0s        1.8V       1.62V      1.95V
51ps      1.8V       1.62V      1.521V
93ps      1.8V       1.62V      1.359V
132ps     1.799V     1.62V      1.286V
189ps     1.316V     1.62V      1.189V
330ps     1.102V     1.619V     1.031V
435ps     1.038V     1.631V     994mV
540ps     949.5mV    1.136V     977.7mV
819ps     903.2mV    951.2mV    966.2mV
1.83ns    893.9mV    813.9mV    964.8mV
[Falling Waveform]
R_fixture = 50
V_fixture = 0
V_fixture_min = 0
V_fixture_max = 0
|   time   V(typ)   V(min)   V(max)
0s        902.3mV    814.7mV    982.6mV
18ps      902.4mV    814.7mV    756mV
75ps      902.9mV    814.7mV    547.8mV
159ps     602.9mV    814.7mV    337.8mV
333ps     277.4mV    814.4mV    61.85mV
411ps     230mV      815.8mV    29.62mV
474ps     120.5mV    544.3mV    15.92mV
795ps     7.566mV    230.9mV    627.5uV
1.164ns   382.9uV    36.13mV    72.32uV
1.674ns   67.29uV    3.378mV    61.95uV
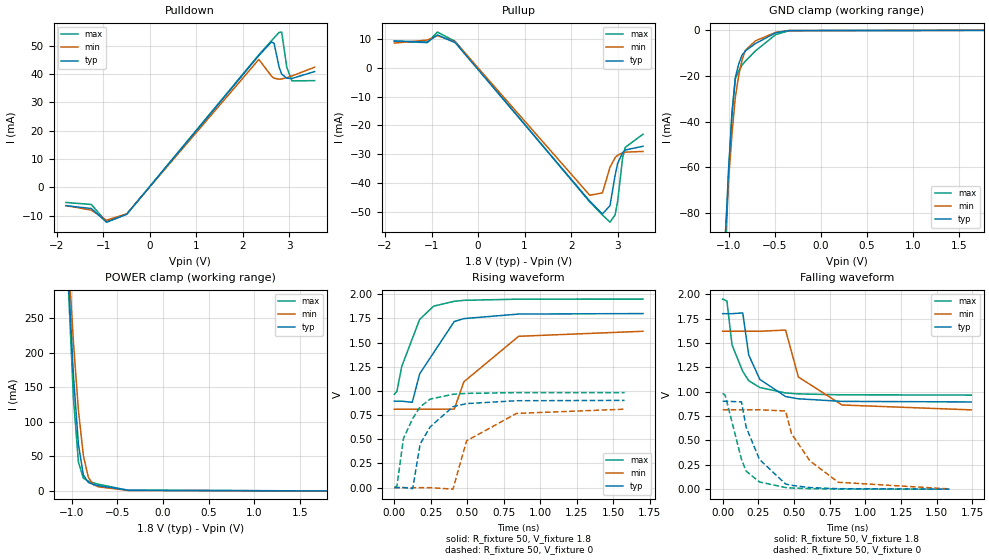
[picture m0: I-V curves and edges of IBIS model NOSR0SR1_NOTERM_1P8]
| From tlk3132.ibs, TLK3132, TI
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|   Model Cell NOSR0SR1_NOTERM_1P8
|NOSR0SR1_NOTERM_1P8
[Model]   NOSR0SR1_NOTERM_1P8
Model_type   3-state
Polarity   Non-Inverting
Enable   Active-Low
Cref =  15.0000pF
Rref =  100.0000M
Vref =  0V
Vmeas =  0.9
C_comp   1.295933p   1.227743p   1.363512p
[Temperature Range]   25   125   -40
[Voltage Range]   1.8   1.62   1.95
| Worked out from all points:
|   slope of the pulldown table from 0 to 0.27 V, typ, clamps not added: 49.1 ohm
|   slope of the pullup table from 0 to 0.27 V, typ, clamps not added: 49.3 ohm
|   GND clamp passes 1 mA (typ) near -0.48 V on its own axis
|   POWER clamp passes 1 mA (typ) near -0.38 V on its own axis
|   rising waveform, R_fixture 50, V_fixture 1.8: 20-80 % time 197ps typ, 331ps min, 141ps max; typ from 0.894 V to 1.8 V
|   rising waveform, R_fixture 50, V_fixture 0: 20-80 % time 164ps typ, 249ps min, 126ps max; typ from 0 V to 0.902 V
|   falling waveform, R_fixture 50, V_fixture 1.8: 20-80 % time 140ps typ, 179ps min, 116ps max; typ from 1.8 V to 0.895 V
|   falling waveform, R_fixture 50, V_fixture 0: 20-80 % time 164ps typ, 275ps min, 127ps max; typ from 0.902 V to 0.001 V
[POWER_clamp]
|   voltage   I(typ)   I(min)   I(max)
-1.8V     2.923A     2.485A     3.339A
-1.055V   360.5mA    378.7mA    354.2mA
-1.036V   307.2mA    334.7mA    291.8mA
-1.018V   260.7mA    295mA      239.4mA
-981.8mV  167.8mA    215.5mA    134.5mA
-927.3mV  67.68mA    117.2mA    41.81mA
-872.7mV  23.04mA    50.89mA    18.36mA
-818.2mV  12.16mA    19.6mA     14.12mA
-763.6mV  9.299mA    9.245mA    11.81mA
-709.1mV  7.658mA    5.964mA    9.714mA
-381.8mV  1.047mA    648.8uA    918.9uA
1.8V      20.41nA    122.3nA    26.44nA
[Pulldown]
|   voltage   I(typ)   I(min)   I(max)
-1.8V     -6.451mA   -6.405mA   -5.315mA
-1.255V   -7.43mA    -8.011mA   -6.013mA
-927.3mV  -12.26mA   -11.57mA   -12.21mA
-490.9mV  -9.427mA   -9.263mA   -9.389mA
2.345V    46.47mA    45.11mA    46.73mA
2.618V    51.3mA     39.22mA    51.73mA
2.673V    50.78mA    38.48mA    52.72mA
2.782V    42.33mA    38.14mA    54.63mA
2.836V    39.97mA    38.24mA    54.75mA
2.945V    38.49mA    38.68mA    42.44mA
3.055V    38.4mA     39.27mA    37.55mA
3.545V    40.84mA    42.38mA    37.64mA
[Pullup]
|   voltage   I(typ)   I(min)   I(max)
-1.8V     9.309mA    8.565mA    9.187mA
-1.091V   8.918mA    9.616mA    8.735mA
-872.7mV  11.39mA    11.15mA    12.38mA
-490.9mV  8.699mA    8.982mA    9.152mA
2.4V      -46.25mA   -44.22mA   -46.54mA
2.673V    -50.7mA    -43.41mA   -51.05mA
2.836V    -47.86mA   -34.53mA   -53.58mA
2.945V    -37.39mA   -31.21mA   -51.04mA
3V        -33.19mA   -30.38mA   -46.39mA
3.109V    -29.38mA   -29.49mA   -31.06mA
3.164V    -28.54mA   -29.26mA   -27.61mA
3.545V    -27.23mA   -29.05mA   -23.05mA
[GND_clamp]
|   voltage   I(typ)   I(min)   I(max)
-1.8V     -3.608A    -2.847A    -4.283A
-1.036V   -91.2mA    -89.54mA   -100.6mA
-1V       -60.4mA    -65.35mA   -62.23mA
-963.6mV  -36.87mA   -45.25mA   -35.78mA
-927.3mV  -20.6mA    -29.23mA   -21.19mA
-890.9mV  -14.74mA   -19.77mA   -17.76mA
-854.5mV  -10.87mA   -12.93mA   -15.19mA
-818.2mV  -9.005mA   -8.715mA   -13.5mA
-709.1mV  -5.779mA   -4.59mA    -9.01mA
-490.9mV  -1.081mA   -898uA     -1.867mA
-345.5mV  -89.76uA   -109.3uA   -157uA
1.764V    -18.75nA   7.297uA    -4.706nA
[Ramp]
| variable   typ   min   max
dV/dt_f  0.5509105/0.1401943n  0.4931119/0.1791421n  0.5965968/0.1154896n
dV/dt_r  0.5491591/0.1616606n  0.4990854/0.2497519n  0.5953481/0.1263033n
R_load = 50
[Rising Waveform]
R_fixture = 50
V_fixture = 1.8
V_fixture_min = 1.62
V_fixture_max = 1.95
|   time   V(typ)   V(min)   V(max)
0s        893.9mV    810.6mV    964.8mV
18ps      893.8mV    810.6mV    995.8mV
51ps      894.2mV    810.6mV    1.253V
123ps     882mV      810.6mV    1.539V
174ps     1.177V     810.6mV    1.74V
270ps     1.397V     810.8mV    1.877V
411ps     1.718V     812.1mV    1.927V
477ps     1.748V     1.095V     1.937V
852ps     1.795V     1.565V     1.949V
1.704ns   1.8V       1.617V     1.95V
[Rising Waveform]
R_fixture = 50
V_fixture = 0
V_fixture_min = 0
V_fixture_max = 0
|   time   V(typ)   V(min)   V(max)
0s        57.94uV    48.16uV    61.33uV
18ps      3.054uV    48.18uV    16.4mV
63ps      765.6uV    47.93uV    509.5mV
126ps     -10.02mV   48.59uV    714.5mV
177ps     449.8mV    54.59uV    835.2mV
246ps     628.8mV    -37.44uV   915.6mV
402ps     836.6mV    -15.82mV   965.3mV
495ps     869mV      483.9mV    974.9mV
837ps     898.7mV    767.2mV    982.2mV
1.578ns   902.1mV    811.4mV    982.6mV
[Falling Waveform]
R_fixture = 50
V_fixture = 1.8
V_fixture_min = 1.62
V_fixture_max = 1.95
|   time   V(typ)   V(min)   V(max)
0s        1.8V       1.62V      1.95V
30ps      1.8V       1.62V      1.93V
66ps      1.8V       1.62V      1.479V
141ps     1.808V     1.62V      1.208V
183ps     1.376V     1.62V      1.113V
261ps     1.126V     1.62V      1.043V
441ps     950.5mV    1.632V     987.3mV
531ps     927.4mV    1.151V     977.7mV
837ps     901mV      863.8mV    967.9mV
1.743ns   895mV      813.9mV    965.6mV
[Falling Waveform]
R_fixture = 50
V_fixture = 0
V_fixture_min = 0
V_fixture_max = 0
|   time   V(typ)   V(min)   V(max)
0s        902.3mV    814.7mV    982.6mV
18ps      902.4mV    814.7mV    963.7mV
132ps     895.8mV    814.7mV    306.8mV
165ps     636mV      814.7mV    185.1mV
258ps     306mV      814.8mV    74.83mV
441ps     53.88mV    802.8mV    17.28mV
483ps     40.15mV    568.5mV    12.83mV
612ps     16.96mV    290.5mV    5.927mV
810ps     5.69mV     71.61mV    2.642mV
1.59ns    1.205mV    3.312mV    802.5uV
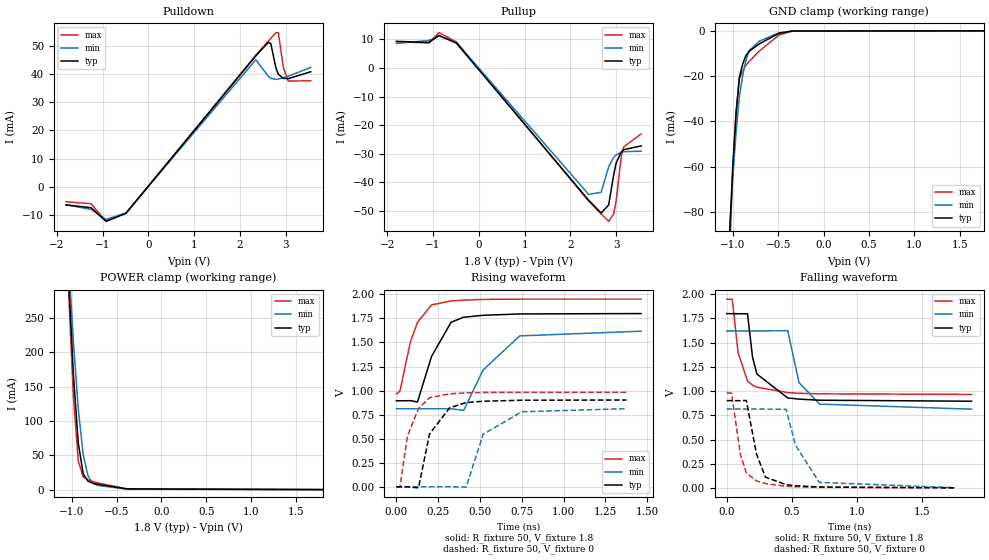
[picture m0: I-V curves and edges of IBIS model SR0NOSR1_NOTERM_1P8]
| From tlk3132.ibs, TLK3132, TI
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|   Model Cell SR0NOSR1_NOTERM_1P8
|SR0NOSR1_NOTERM_1P8
[Model]   SR0NOSR1_NOTERM_1P8
Model_type   3-state
Polarity   Non-Inverting
Enable   Active-Low
Cref =  15.0000pF
Rref =  100.0000M
Vref =  0V
Vmeas =  0.9
C_comp   1.295933p   1.227743p   1.363512p
[Temperature Range]   25   125   -40
[Voltage Range]   1.8   1.62   1.95
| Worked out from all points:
|   slope of the pulldown table from 0 to 0.27 V, typ, clamps not added: 49.1 ohm
|   slope of the pullup table from 0 to 0.27 V, typ, clamps not added: 49.3 ohm
|   GND clamp passes 1 mA (typ) near -0.48 V on its own axis
|   POWER clamp passes 1 mA (typ) near -0.38 V on its own axis
|   rising waveform, R_fixture 50, V_fixture 1.8: 20-80 % time 137ps typ, 228ps min, 96.7ps max; typ from 0.894 V to 1.8 V
|   rising waveform, R_fixture 50, V_fixture 0: 20-80 % time 103ps typ, 143ps min, 84.9ps max; typ from 0 V to 0.902 V
|   falling waveform, R_fixture 50, V_fixture 1.8: 20-80 % time 84.1ps typ, 116ps min, 74.8ps max; typ from 1.8 V to 0.896 V
|   falling waveform, R_fixture 50, V_fixture 0: 20-80 % time 93.8ps typ, 137ps min, 80.5ps max; typ from 0.902 V to 0.002 V
[POWER_clamp]
|   voltage   I(typ)   I(min)   I(max)
-1.8V     2.923A     2.485A     3.339A
-1.055V   360.5mA    378.7mA    354.2mA
-1.036V   307.2mA    334.7mA    291.8mA
-1.018V   260.7mA    295mA      239.4mA
-981.8mV  167.8mA    215.5mA    134.5mA
-927.3mV  67.68mA    117.2mA    41.81mA
-872.7mV  23.04mA    50.89mA    18.36mA
-818.2mV  12.16mA    19.6mA     14.12mA
-763.6mV  9.299mA    9.245mA    11.81mA
-709.1mV  7.658mA    5.964mA    9.714mA
-381.8mV  1.047mA    648.8uA    918.9uA
1.8V      20.41nA    122.3nA    26.44nA
[Pulldown]
|   voltage   I(typ)   I(min)   I(max)
-1.8V     -6.451mA   -6.405mA   -5.315mA
-1.255V   -7.43mA    -8.011mA   -6.013mA
-927.3mV  -12.26mA   -11.57mA   -12.21mA
-490.9mV  -9.427mA   -9.263mA   -9.389mA
2.345V    46.47mA    45.11mA    46.73mA
2.618V    51.3mA     39.22mA    51.73mA
2.673V    50.78mA    38.48mA    52.72mA
2.782V    42.33mA    38.14mA    54.63mA
2.836V    39.97mA    38.24mA    54.75mA
2.945V    38.49mA    38.68mA    42.44mA
3.055V    38.4mA     39.27mA    37.55mA
3.545V    40.84mA    42.38mA    37.64mA
[Pullup]
|   voltage   I(typ)   I(min)   I(max)
-1.8V     9.309mA    8.565mA    9.187mA
-1.091V   8.918mA    9.616mA    8.735mA
-872.7mV  11.39mA    11.15mA    12.38mA
-490.9mV  8.699mA    8.982mA    9.152mA
2.4V      -46.25mA   -44.22mA   -46.54mA
2.673V    -50.7mA    -43.41mA   -51.05mA
2.836V    -47.86mA   -34.53mA   -53.58mA
2.945V    -37.39mA   -31.21mA   -51.04mA
3V        -33.19mA   -30.38mA   -46.39mA
3.109V    -29.38mA   -29.49mA   -31.06mA
3.164V    -28.54mA   -29.26mA   -27.61mA
3.545V    -27.23mA   -29.05mA   -23.05mA
[GND_clamp]
|   voltage   I(typ)   I(min)   I(max)
-1.8V     -3.608A    -2.847A    -4.283A
-1.036V   -91.2mA    -89.54mA   -100.6mA
-1V       -60.4mA    -65.35mA   -62.23mA
-963.6mV  -36.87mA   -45.25mA   -35.78mA
-927.3mV  -20.6mA    -29.23mA   -21.19mA
-890.9mV  -14.74mA   -19.77mA   -17.76mA
-854.5mV  -10.87mA   -12.93mA   -15.19mA
-818.2mV  -9.005mA   -8.715mA   -13.5mA
-709.1mV  -5.779mA   -4.59mA    -9.01mA
-490.9mV  -1.081mA   -898uA     -1.867mA
-345.5mV  -89.76uA   -109.3uA   -157uA
1.764V    -18.75nA   7.297uA    -4.706nA
[Ramp]
| variable   typ   min   max
dV/dt_f  0.5516926/83.67208p   0.4939541/0.1161259n  0.5971028/74.83968p
dV/dt_r  0.5493867/0.1017506n  0.4994163/0.1428436n  0.5954188/84.78298p
R_load = 50
[Rising Waveform]
R_fixture = 50
V_fixture = 1.8
V_fixture_min = 1.62
V_fixture_max = 1.95
|   time   V(typ)   V(min)   V(max)
0s        893.9mV    810.6mV    964.8mV
21ps      893.8mV    810.6mV    994.9mV
84ps      895.5mV    810.6mV    1.51V
126ps     881.3mV    810.6mV    1.708V
210ps     1.355V     810.5mV    1.89V
327ps     1.71V      811.7mV    1.931V
402ps     1.762V     793.5mV    1.94V
519ps     1.782V     1.215V     1.947V
738ps     1.796V     1.568V     1.95V
1.464ns   1.8V       1.617V     1.95V
[Rising Waveform]
R_fixture = 50
V_fixture = 0
V_fixture_min = 0
V_fixture_max = 0
|   time   V(typ)   V(min)   V(max)
0s        57.94uV    48.16uV    61.33uV
21ps      17uV       48.2uV     -1.107mV
66ps      624.8uV    47.96uV    525.7mV
132ps     -10.76mV   48.62uV    813.8mV
198ps     548.8mV    50.17uV    925.6mV
318ps     820mV      1.208mV    966.1mV
417ps     875.4mV    -3.272mV   976.4mV
519ps     889.2mV    546.4mV    980.3mV
750ps     899.7mV    779.7mV    982.2mV
1.377ns   902mV      811.5mV    982.5mV
[Falling Waveform]
R_fixture = 50
V_fixture = 1.8
V_fixture_min = 1.62
V_fixture_max = 1.95
|   time   V(typ)   V(min)   V(max)
0s        1.8V       1.62V      1.95V
42ps      1.8V       1.62V      1.949V
87ps      1.799V     1.62V      1.395V
159ps     1.799V     1.62V      1.104V
198ps     1.35V      1.62V      1.062V
231ps     1.177V     1.62V      1.041V
468ps     929.6mV    1.625V     984.7mV
555ps     917.6mV    1.088V     978.2mV
714ps     906.3mV    866.1mV    972.2mV
1.881ns   895.8mV    813.8mV    966.2mV
[Falling Waveform]
R_fixture = 50
V_fixture = 0
V_fixture_min = 0
V_fixture_max = 0
|   time   V(typ)   V(min)   V(max)
0s        902.3mV    814.7mV    982.6mV
36ps      902.3mV    814.7mV    979.7mV
105ps     901.2mV    814.7mV    344mV
150ps     904.1mV    814.7mV    155mV
228ps     352mV      814.7mV    73.97mV
297ps     112.3mV    814.8mV    45.39mV
456ps     34.27mV    811.6mV    17.74mV
528ps     23.12mV    442mV      12.59mV
711ps     10.44mV    57.52mV    6.289mV
1.749ns   1.956mV    3.303mV    1.351mV
